VERSION 5.8 ;
BUSBITCHARS "[]" ;
DIVIDERCHAR "/" ;
UNITS
    DATABASE MICRONS 1000 ;
END UNITS

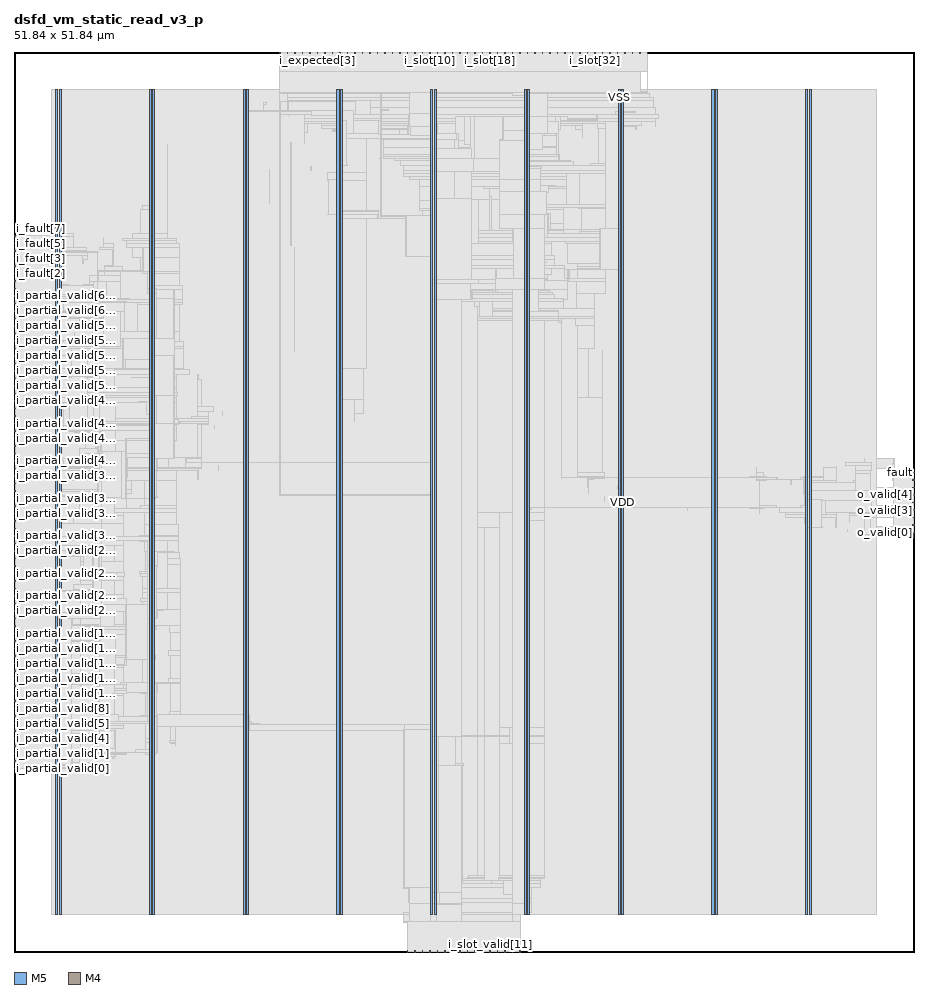
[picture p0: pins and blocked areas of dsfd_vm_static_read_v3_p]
MACRO dsfd_vm_static_read_v3_p
  FOREIGN dsfd_vm_static_read_v3_p 0 0 ;
  CLASS BLOCK ;
  SIZE 51.84 BY 51.84 ;
  PIN ck
    DIRECTION INPUT ;
    USE SIGNAL ;
    PORT
      LAYER M5 ;
        RECT  15.312 51.756 15.336 51.84 ;
    END
  END ck
  PIN fault
    DIRECTION OUTPUT ;
    USE SIGNAL ;
    PORT
      LAYER M4 ;
        RECT  51.756 27.6 51.84 27.624 ;
    END
  END fault
  PIN i_expected[0]
    DIRECTION INPUT ;
    USE SIGNAL ;
    PORT
      LAYER M5 ;
        RECT  16.176 51.756 16.2 51.84 ;
    END
  END i_expected[0]
  PIN i_expected[1]
    DIRECTION INPUT ;
    USE SIGNAL ;
    PORT
      LAYER M5 ;
        RECT  16.608 51.756 16.632 51.84 ;
    END
  END i_expected[1]
  PIN i_expected[2]
    DIRECTION INPUT ;
    USE SIGNAL ;
    PORT
      LAYER M5 ;
        RECT  17.04 51.756 17.064 51.84 ;
    END
  END i_expected[2]
  PIN i_expected[3]
    DIRECTION INPUT ;
    USE SIGNAL ;
    PORT
      LAYER M5 ;
        RECT  17.472 51.756 17.496 51.84 ;
    END
  END i_expected[3]
  PIN i_expected[4]
    DIRECTION INPUT ;
    USE SIGNAL ;
    PORT
      LAYER M5 ;
        RECT  17.904 51.756 17.928 51.84 ;
    END
  END i_expected[4]
  PIN i_expected[5]
    DIRECTION INPUT ;
    USE SIGNAL ;
    PORT
      LAYER M5 ;
        RECT  18.336 51.756 18.36 51.84 ;
    END
  END i_expected[5]
  PIN i_expected[6]
    DIRECTION INPUT ;
    USE SIGNAL ;
    PORT
      LAYER M5 ;
        RECT  18.768 51.756 18.792 51.84 ;
    END
  END i_expected[6]
  PIN i_expected[7]
    DIRECTION INPUT ;
    USE SIGNAL ;
    PORT
      LAYER M5 ;
        RECT  19.2 51.756 19.224 51.84 ;
    END
  END i_expected[7]
  PIN i_fault[0]
    DIRECTION INPUT ;
    USE SIGNAL ;
    PORT
      LAYER M4 ;
        RECT  0 38.208 0.084 38.232 ;
    END
  END i_fault[0]
  PIN i_fault[1]
    DIRECTION INPUT ;
    USE SIGNAL ;
    PORT
      LAYER M4 ;
        RECT  0 38.64 0.084 38.664 ;
    END
  END i_fault[1]
  PIN i_fault[2]
    DIRECTION INPUT ;
    USE SIGNAL ;
    PORT
      LAYER M4 ;
        RECT  0 39.072 0.084 39.096 ;
    END
  END i_fault[2]
  PIN i_fault[3]
    DIRECTION INPUT ;
    USE SIGNAL ;
    PORT
      LAYER M4 ;
        RECT  0 39.504 0.084 39.528 ;
    END
  END i_fault[3]
  PIN i_fault[4]
    DIRECTION INPUT ;
    USE SIGNAL ;
    PORT
      LAYER M4 ;
        RECT  0 39.936 0.084 39.96 ;
    END
  END i_fault[4]
  PIN i_fault[5]
    DIRECTION INPUT ;
    USE SIGNAL ;
    PORT
      LAYER M4 ;
        RECT  0 40.368 0.084 40.392 ;
    END
  END i_fault[5]
  PIN i_fault[6]
    DIRECTION INPUT ;
    USE SIGNAL ;
    PORT
      LAYER M4 ;
        RECT  0 40.8 0.084 40.824 ;
    END
  END i_fault[6]
  PIN i_fault[7]
    DIRECTION INPUT ;
    USE SIGNAL ;
    PORT
      LAYER M4 ;
        RECT  0 41.232 0.084 41.256 ;
    END
  END i_fault[7]
  PIN i_partial_valid[0]
    DIRECTION INPUT ;
    USE SIGNAL ;
    PORT
      LAYER M4 ;
        RECT  0 10.56 0.084 10.584 ;
    END
  END i_partial_valid[0]
  PIN i_partial_valid[10]
    DIRECTION INPUT ;
    USE SIGNAL ;
    PORT
      LAYER M4 ;
        RECT  0 14.88 0.084 14.904 ;
    END
  END i_partial_valid[10]
  PIN i_partial_valid[11]
    DIRECTION INPUT ;
    USE SIGNAL ;
    PORT
      LAYER M4 ;
        RECT  0 15.312 0.084 15.336 ;
    END
  END i_partial_valid[11]
  PIN i_partial_valid[12]
    DIRECTION INPUT ;
    USE SIGNAL ;
    PORT
      LAYER M4 ;
        RECT  0 15.744 0.084 15.768 ;
    END
  END i_partial_valid[12]
  PIN i_partial_valid[13]
    DIRECTION INPUT ;
    USE SIGNAL ;
    PORT
      LAYER M4 ;
        RECT  0 16.176 0.084 16.2 ;
    END
  END i_partial_valid[13]
  PIN i_partial_valid[14]
    DIRECTION INPUT ;
    USE SIGNAL ;
    PORT
      LAYER M4 ;
        RECT  0 16.608 0.084 16.632 ;
    END
  END i_partial_valid[14]
  PIN i_partial_valid[15]
    DIRECTION INPUT ;
    USE SIGNAL ;
    PORT
      LAYER M4 ;
        RECT  0 17.04 0.084 17.064 ;
    END
  END i_partial_valid[15]
  PIN i_partial_valid[16]
    DIRECTION INPUT ;
    USE SIGNAL ;
    PORT
      LAYER M4 ;
        RECT  0 17.472 0.084 17.496 ;
    END
  END i_partial_valid[16]
  PIN i_partial_valid[17]
    DIRECTION INPUT ;
    USE SIGNAL ;
    PORT
      LAYER M4 ;
        RECT  0 17.904 0.084 17.928 ;
    END
  END i_partial_valid[17]
  PIN i_partial_valid[18]
    DIRECTION INPUT ;
    USE SIGNAL ;
    PORT
      LAYER M4 ;
        RECT  0 18.336 0.084 18.36 ;
    END
  END i_partial_valid[18]
  PIN i_partial_valid[19]
    DIRECTION INPUT ;
    USE SIGNAL ;
    PORT
      LAYER M4 ;
        RECT  0 18.768 0.084 18.792 ;
    END
  END i_partial_valid[19]
  PIN i_partial_valid[1]
    DIRECTION INPUT ;
    USE SIGNAL ;
    PORT
      LAYER M4 ;
        RECT  0 10.992 0.084 11.016 ;
    END
  END i_partial_valid[1]
  PIN i_partial_valid[20]
    DIRECTION INPUT ;
    USE SIGNAL ;
    PORT
      LAYER M4 ;
        RECT  0 19.2 0.084 19.224 ;
    END
  END i_partial_valid[20]
  PIN i_partial_valid[21]
    DIRECTION INPUT ;
    USE SIGNAL ;
    PORT
      LAYER M4 ;
        RECT  0 19.632 0.084 19.656 ;
    END
  END i_partial_valid[21]
  PIN i_partial_valid[22]
    DIRECTION INPUT ;
    USE SIGNAL ;
    PORT
      LAYER M4 ;
        RECT  0 20.064 0.084 20.088 ;
    END
  END i_partial_valid[22]
  PIN i_partial_valid[23]
    DIRECTION INPUT ;
    USE SIGNAL ;
    PORT
      LAYER M4 ;
        RECT  0 20.496 0.084 20.52 ;
    END
  END i_partial_valid[23]
  PIN i_partial_valid[24]
    DIRECTION INPUT ;
    USE SIGNAL ;
    PORT
      LAYER M4 ;
        RECT  0 20.928 0.084 20.952 ;
    END
  END i_partial_valid[24]
  PIN i_partial_valid[25]
    DIRECTION INPUT ;
    USE SIGNAL ;
    PORT
      LAYER M4 ;
        RECT  0 21.36 0.084 21.384 ;
    END
  END i_partial_valid[25]
  PIN i_partial_valid[26]
    DIRECTION INPUT ;
    USE SIGNAL ;
    PORT
      LAYER M4 ;
        RECT  0 21.792 0.084 21.816 ;
    END
  END i_partial_valid[26]
  PIN i_partial_valid[27]
    DIRECTION INPUT ;
    USE SIGNAL ;
    PORT
      LAYER M4 ;
        RECT  0 22.224 0.084 22.248 ;
    END
  END i_partial_valid[27]
  PIN i_partial_valid[28]
    DIRECTION INPUT ;
    USE SIGNAL ;
    PORT
      LAYER M4 ;
        RECT  0 22.656 0.084 22.68 ;
    END
  END i_partial_valid[28]
  PIN i_partial_valid[29]
    DIRECTION INPUT ;
    USE SIGNAL ;
    PORT
      LAYER M4 ;
        RECT  0 23.088 0.084 23.112 ;
    END
  END i_partial_valid[29]
  PIN i_partial_valid[2]
    DIRECTION INPUT ;
    USE SIGNAL ;
    PORT
      LAYER M4 ;
        RECT  0 11.424 0.084 11.448 ;
    END
  END i_partial_valid[2]
  PIN i_partial_valid[30]
    DIRECTION INPUT ;
    USE SIGNAL ;
    PORT
      LAYER M4 ;
        RECT  0 23.52 0.084 23.544 ;
    END
  END i_partial_valid[30]
  PIN i_partial_valid[31]
    DIRECTION INPUT ;
    USE SIGNAL ;
    PORT
      LAYER M4 ;
        RECT  0 23.952 0.084 23.976 ;
    END
  END i_partial_valid[31]
  PIN i_partial_valid[32]
    DIRECTION INPUT ;
    USE SIGNAL ;
    PORT
      LAYER M4 ;
        RECT  0 24.384 0.084 24.408 ;
    END
  END i_partial_valid[32]
  PIN i_partial_valid[33]
    DIRECTION INPUT ;
    USE SIGNAL ;
    PORT
      LAYER M4 ;
        RECT  0 24.816 0.084 24.84 ;
    END
  END i_partial_valid[33]
  PIN i_partial_valid[34]
    DIRECTION INPUT ;
    USE SIGNAL ;
    PORT
      LAYER M4 ;
        RECT  0 25.248 0.084 25.272 ;
    END
  END i_partial_valid[34]
  PIN i_partial_valid[35]
    DIRECTION INPUT ;
    USE SIGNAL ;
    PORT
      LAYER M4 ;
        RECT  0 25.68 0.084 25.704 ;
    END
  END i_partial_valid[35]
  PIN i_partial_valid[36]
    DIRECTION INPUT ;
    USE SIGNAL ;
    PORT
      LAYER M4 ;
        RECT  0 26.112 0.084 26.136 ;
    END
  END i_partial_valid[36]
  PIN i_partial_valid[37]
    DIRECTION INPUT ;
    USE SIGNAL ;
    PORT
      LAYER M4 ;
        RECT  0 26.544 0.084 26.568 ;
    END
  END i_partial_valid[37]
  PIN i_partial_valid[38]
    DIRECTION INPUT ;
    USE SIGNAL ;
    PORT
      LAYER M4 ;
        RECT  0 26.976 0.084 27 ;
    END
  END i_partial_valid[38]
  PIN i_partial_valid[39]
    DIRECTION INPUT ;
    USE SIGNAL ;
    PORT
      LAYER M4 ;
        RECT  0 27.408 0.084 27.432 ;
    END
  END i_partial_valid[39]
  PIN i_partial_valid[3]
    DIRECTION INPUT ;
    USE SIGNAL ;
    PORT
      LAYER M4 ;
        RECT  0 11.856 0.084 11.88 ;
    END
  END i_partial_valid[3]
  PIN i_partial_valid[40]
    DIRECTION INPUT ;
    USE SIGNAL ;
    PORT
      LAYER M4 ;
        RECT  0 27.84 0.084 27.864 ;
    END
  END i_partial_valid[40]
  PIN i_partial_valid[41]
    DIRECTION INPUT ;
    USE SIGNAL ;
    PORT
      LAYER M4 ;
        RECT  0 28.272 0.084 28.296 ;
    END
  END i_partial_valid[41]
  PIN i_partial_valid[42]
    DIRECTION INPUT ;
    USE SIGNAL ;
    PORT
      LAYER M4 ;
        RECT  0 28.704 0.084 28.728 ;
    END
  END i_partial_valid[42]
  PIN i_partial_valid[43]
    DIRECTION INPUT ;
    USE SIGNAL ;
    PORT
      LAYER M4 ;
        RECT  0 29.136 0.084 29.16 ;
    END
  END i_partial_valid[43]
  PIN i_partial_valid[44]
    DIRECTION INPUT ;
    USE SIGNAL ;
    PORT
      LAYER M4 ;
        RECT  0 29.568 0.084 29.592 ;
    END
  END i_partial_valid[44]
  PIN i_partial_valid[45]
    DIRECTION INPUT ;
    USE SIGNAL ;
    PORT
      LAYER M4 ;
        RECT  0 30 0.084 30.024 ;
    END
  END i_partial_valid[45]
  PIN i_partial_valid[46]
    DIRECTION INPUT ;
    USE SIGNAL ;
    PORT
      LAYER M4 ;
        RECT  0 30.432 0.084 30.456 ;
    END
  END i_partial_valid[46]
  PIN i_partial_valid[47]
    DIRECTION INPUT ;
    USE SIGNAL ;
    PORT
      LAYER M4 ;
        RECT  0 30.864 0.084 30.888 ;
    END
  END i_partial_valid[47]
  PIN i_partial_valid[48]
    DIRECTION INPUT ;
    USE SIGNAL ;
    PORT
      LAYER M4 ;
        RECT  0 31.296 0.084 31.32 ;
    END
  END i_partial_valid[48]
  PIN i_partial_valid[49]
    DIRECTION INPUT ;
    USE SIGNAL ;
    PORT
      LAYER M4 ;
        RECT  0 31.728 0.084 31.752 ;
    END
  END i_partial_valid[49]
  PIN i_partial_valid[4]
    DIRECTION INPUT ;
    USE SIGNAL ;
    PORT
      LAYER M4 ;
        RECT  0 12.288 0.084 12.312 ;
    END
  END i_partial_valid[4]
  PIN i_partial_valid[50]
    DIRECTION INPUT ;
    USE SIGNAL ;
    PORT
      LAYER M4 ;
        RECT  0 32.16 0.084 32.184 ;
    END
  END i_partial_valid[50]
  PIN i_partial_valid[51]
    DIRECTION INPUT ;
    USE SIGNAL ;
    PORT
      LAYER M4 ;
        RECT  0 32.592 0.084 32.616 ;
    END
  END i_partial_valid[51]
  PIN i_partial_valid[52]
    DIRECTION INPUT ;
    USE SIGNAL ;
    PORT
      LAYER M4 ;
        RECT  0 33.024 0.084 33.048 ;
    END
  END i_partial_valid[52]
  PIN i_partial_valid[53]
    DIRECTION INPUT ;
    USE SIGNAL ;
    PORT
      LAYER M4 ;
        RECT  0 33.456 0.084 33.48 ;
    END
  END i_partial_valid[53]
  PIN i_partial_valid[54]
    DIRECTION INPUT ;
    USE SIGNAL ;
    PORT
      LAYER M4 ;
        RECT  0 33.888 0.084 33.912 ;
    END
  END i_partial_valid[54]
  PIN i_partial_valid[55]
    DIRECTION INPUT ;
    USE SIGNAL ;
    PORT
      LAYER M4 ;
        RECT  0 34.32 0.084 34.344 ;
    END
  END i_partial_valid[55]
  PIN i_partial_valid[56]
    DIRECTION INPUT ;
    USE SIGNAL ;
    PORT
      LAYER M4 ;
        RECT  0 34.752 0.084 34.776 ;
    END
  END i_partial_valid[56]
  PIN i_partial_valid[57]
    DIRECTION INPUT ;
    USE SIGNAL ;
    PORT
      LAYER M4 ;
        RECT  0 35.184 0.084 35.208 ;
    END
  END i_partial_valid[57]
  PIN i_partial_valid[58]
    DIRECTION INPUT ;
    USE SIGNAL ;
    PORT
      LAYER M4 ;
        RECT  0 35.616 0.084 35.64 ;
    END
  END i_partial_valid[58]
  PIN i_partial_valid[59]
    DIRECTION INPUT ;
    USE SIGNAL ;
    PORT
      LAYER M4 ;
        RECT  0 36.048 0.084 36.072 ;
    END
  END i_partial_valid[59]
  PIN i_partial_valid[5]
    DIRECTION INPUT ;
    USE SIGNAL ;
    PORT
      LAYER M4 ;
        RECT  0 12.72 0.084 12.744 ;
    END
  END i_partial_valid[5]
  PIN i_partial_valid[60]
    DIRECTION INPUT ;
    USE SIGNAL ;
    PORT
      LAYER M4 ;
        RECT  0 36.48 0.084 36.504 ;
    END
  END i_partial_valid[60]
  PIN i_partial_valid[61]
    DIRECTION INPUT ;
    USE SIGNAL ;
    PORT
      LAYER M4 ;
        RECT  0 36.912 0.084 36.936 ;
    END
  END i_partial_valid[61]
  PIN i_partial_valid[62]
    DIRECTION INPUT ;
    USE SIGNAL ;
    PORT
      LAYER M4 ;
        RECT  0 37.344 0.084 37.368 ;
    END
  END i_partial_valid[62]
  PIN i_partial_valid[63]
    DIRECTION INPUT ;
    USE SIGNAL ;
    PORT
      LAYER M4 ;
        RECT  0 37.776 0.084 37.8 ;
    END
  END i_partial_valid[63]
  PIN i_partial_valid[6]
    DIRECTION INPUT ;
    USE SIGNAL ;
    PORT
      LAYER M4 ;
        RECT  0 13.152 0.084 13.176 ;
    END
  END i_partial_valid[6]
  PIN i_partial_valid[7]
    DIRECTION INPUT ;
    USE SIGNAL ;
    PORT
      LAYER M4 ;
        RECT  0 13.584 0.084 13.608 ;
    END
  END i_partial_valid[7]
  PIN i_partial_valid[8]
    DIRECTION INPUT ;
    USE SIGNAL ;
    PORT
      LAYER M4 ;
        RECT  0 14.016 0.084 14.04 ;
    END
  END i_partial_valid[8]
  PIN i_partial_valid[9]
    DIRECTION INPUT ;
    USE SIGNAL ;
    PORT
      LAYER M4 ;
        RECT  0 14.448 0.084 14.472 ;
    END
  END i_partial_valid[9]
  PIN i_slot[0]
    DIRECTION INPUT ;
    USE SIGNAL ;
    PORT
      LAYER M5 ;
        RECT  19.632 51.756 19.656 51.84 ;
    END
  END i_slot[0]
  PIN i_slot[10]
    DIRECTION INPUT ;
    USE SIGNAL ;
    PORT
      LAYER M5 ;
        RECT  23.952 51.756 23.976 51.84 ;
    END
  END i_slot[10]
  PIN i_slot[11]
    DIRECTION INPUT ;
    USE SIGNAL ;
    PORT
      LAYER M5 ;
        RECT  24.384 51.756 24.408 51.84 ;
    END
  END i_slot[11]
  PIN i_slot[12]
    DIRECTION INPUT ;
    USE SIGNAL ;
    PORT
      LAYER M5 ;
        RECT  24.816 51.756 24.84 51.84 ;
    END
  END i_slot[12]
  PIN i_slot[13]
    DIRECTION INPUT ;
    USE SIGNAL ;
    PORT
      LAYER M5 ;
        RECT  25.248 51.756 25.272 51.84 ;
    END
  END i_slot[13]
  PIN i_slot[14]
    DIRECTION INPUT ;
    USE SIGNAL ;
    PORT
      LAYER M5 ;
        RECT  25.68 51.756 25.704 51.84 ;
    END
  END i_slot[14]
  PIN i_slot[15]
    DIRECTION INPUT ;
    USE SIGNAL ;
    PORT
      LAYER M5 ;
        RECT  26.112 51.756 26.136 51.84 ;
    END
  END i_slot[15]
  PIN i_slot[16]
    DIRECTION INPUT ;
    USE SIGNAL ;
    PORT
      LAYER M5 ;
        RECT  26.544 51.756 26.568 51.84 ;
    END
  END i_slot[16]
  PIN i_slot[17]
    DIRECTION INPUT ;
    USE SIGNAL ;
    PORT
      LAYER M5 ;
        RECT  26.976 51.756 27 51.84 ;
    END
  END i_slot[17]
  PIN i_slot[18]
    DIRECTION INPUT ;
    USE SIGNAL ;
    PORT
      LAYER M5 ;
        RECT  27.408 51.756 27.432 51.84 ;
    END
  END i_slot[18]
  PIN i_slot[19]
    DIRECTION INPUT ;
    USE SIGNAL ;
    PORT
      LAYER M5 ;
        RECT  27.84 51.756 27.864 51.84 ;
    END
  END i_slot[19]
  PIN i_slot[1]
    DIRECTION INPUT ;
    USE SIGNAL ;
    PORT
      LAYER M5 ;
        RECT  20.064 51.756 20.088 51.84 ;
    END
  END i_slot[1]
  PIN i_slot[20]
    DIRECTION INPUT ;
    USE SIGNAL ;
    PORT
      LAYER M5 ;
        RECT  28.272 51.756 28.296 51.84 ;
    END
  END i_slot[20]
  PIN i_slot[21]
    DIRECTION INPUT ;
    USE SIGNAL ;
    PORT
      LAYER M5 ;
        RECT  28.704 51.756 28.728 51.84 ;
    END
  END i_slot[21]
  PIN i_slot[22]
    DIRECTION INPUT ;
    USE SIGNAL ;
    PORT
      LAYER M5 ;
        RECT  29.136 51.756 29.16 51.84 ;
    END
  END i_slot[22]
  PIN i_slot[23]
    DIRECTION INPUT ;
    USE SIGNAL ;
    PORT
      LAYER M5 ;
        RECT  29.568 51.756 29.592 51.84 ;
    END
  END i_slot[23]
  PIN i_slot[24]
    DIRECTION INPUT ;
    USE SIGNAL ;
    PORT
      LAYER M5 ;
        RECT  30 51.756 30.024 51.84 ;
    END
  END i_slot[24]
  PIN i_slot[25]
    DIRECTION INPUT ;
    USE SIGNAL ;
    PORT
      LAYER M5 ;
        RECT  30.432 51.756 30.456 51.84 ;
    END
  END i_slot[25]
  PIN i_slot[26]
    DIRECTION INPUT ;
    USE SIGNAL ;
    PORT
      LAYER M5 ;
        RECT  30.864 51.756 30.888 51.84 ;
    END
  END i_slot[26]
  PIN i_slot[27]
    DIRECTION INPUT ;
    USE SIGNAL ;
    PORT
      LAYER M5 ;
        RECT  31.296 51.756 31.32 51.84 ;
    END
  END i_slot[27]
  PIN i_slot[28]
    DIRECTION INPUT ;
    USE SIGNAL ;
    PORT
      LAYER M5 ;
        RECT  31.728 51.756 31.752 51.84 ;
    END
  END i_slot[28]
  PIN i_slot[29]
    DIRECTION INPUT ;
    USE SIGNAL ;
    PORT
      LAYER M5 ;
        RECT  32.16 51.756 32.184 51.84 ;
    END
  END i_slot[29]
  PIN i_slot[2]
    DIRECTION INPUT ;
    USE SIGNAL ;
    PORT
      LAYER M5 ;
        RECT  20.496 51.756 20.52 51.84 ;
    END
  END i_slot[2]
  PIN i_slot[30]
    DIRECTION INPUT ;
    USE SIGNAL ;
    PORT
      LAYER M5 ;
        RECT  32.592 51.756 32.616 51.84 ;
    END
  END i_slot[30]
  PIN i_slot[31]
    DIRECTION INPUT ;
    USE SIGNAL ;
    PORT
      LAYER M5 ;
        RECT  33.024 51.756 33.048 51.84 ;
    END
  END i_slot[31]
  PIN i_slot[32]
    DIRECTION INPUT ;
    USE SIGNAL ;
    PORT
      LAYER M5 ;
        RECT  33.456 51.756 33.48 51.84 ;
    END
  END i_slot[32]
  PIN i_slot[33]
    DIRECTION INPUT ;
    USE SIGNAL ;
    PORT
      LAYER M5 ;
        RECT  33.888 51.756 33.912 51.84 ;
    END
  END i_slot[33]
  PIN i_slot[34]
    DIRECTION INPUT ;
    USE SIGNAL ;
    PORT
      LAYER M5 ;
        RECT  34.32 51.756 34.344 51.84 ;
    END
  END i_slot[34]
  PIN i_slot[35]
    DIRECTION INPUT ;
    USE SIGNAL ;
    PORT
      LAYER M5 ;
        RECT  34.752 51.756 34.776 51.84 ;
    END
  END i_slot[35]
  PIN i_slot[36]
    DIRECTION INPUT ;
    USE SIGNAL ;
    PORT
      LAYER M5 ;
        RECT  35.184 51.756 35.208 51.84 ;
    END
  END i_slot[36]
  PIN i_slot[37]
    DIRECTION INPUT ;
    USE SIGNAL ;
    PORT
      LAYER M5 ;
        RECT  35.616 51.756 35.64 51.84 ;
    END
  END i_slot[37]
  PIN i_slot[38]
    DIRECTION INPUT ;
    USE SIGNAL ;
    PORT
      LAYER M5 ;
        RECT  36.048 51.756 36.072 51.84 ;
    END
  END i_slot[38]
  PIN i_slot[39]
    DIRECTION INPUT ;
    USE SIGNAL ;
    PORT
      LAYER M5 ;
        RECT  36.48 51.756 36.504 51.84 ;
    END
  END i_slot[39]
  PIN i_slot[3]
    DIRECTION INPUT ;
    USE SIGNAL ;
    PORT
      LAYER M5 ;
        RECT  20.928 51.756 20.952 51.84 ;
    END
  END i_slot[3]
  PIN i_slot[4]
    DIRECTION INPUT ;
    USE SIGNAL ;
    PORT
      LAYER M5 ;
        RECT  21.36 51.756 21.384 51.84 ;
    END
  END i_slot[4]
  PIN i_slot[5]
    DIRECTION INPUT ;
    USE SIGNAL ;
    PORT
      LAYER M5 ;
        RECT  21.792 51.756 21.816 51.84 ;
    END
  END i_slot[5]
  PIN i_slot[6]
    DIRECTION INPUT ;
    USE SIGNAL ;
    PORT
      LAYER M5 ;
        RECT  22.224 51.756 22.248 51.84 ;
    END
  END i_slot[6]
  PIN i_slot[7]
    DIRECTION INPUT ;
    USE SIGNAL ;
    PORT
      LAYER M5 ;
        RECT  22.656 51.756 22.68 51.84 ;
    END
  END i_slot[7]
  PIN i_slot[8]
    DIRECTION INPUT ;
    USE SIGNAL ;
    PORT
      LAYER M5 ;
        RECT  23.088 51.756 23.112 51.84 ;
    END
  END i_slot[8]
  PIN i_slot[9]
    DIRECTION INPUT ;
    USE SIGNAL ;
    PORT
      LAYER M5 ;
        RECT  23.52 51.756 23.544 51.84 ;
    END
  END i_slot[9]
  PIN i_slot_valid[0]
    DIRECTION INPUT ;
    USE SIGNAL ;
    PORT
      LAYER M5 ;
        RECT  22.656 0 22.68 0.084 ;
    END
  END i_slot_valid[0]
  PIN i_slot_valid[10]
    DIRECTION INPUT ;
    USE SIGNAL ;
    PORT
      LAYER M5 ;
        RECT  26.976 0 27 0.084 ;
    END
  END i_slot_valid[10]
  PIN i_slot_valid[11]
    DIRECTION INPUT ;
    USE SIGNAL ;
    PORT
      LAYER M5 ;
        RECT  27.408 0 27.432 0.084 ;
    END
  END i_slot_valid[11]
  PIN i_slot_valid[12]
    DIRECTION INPUT ;
    USE SIGNAL ;
    PORT
      LAYER M5 ;
        RECT  27.84 0 27.864 0.084 ;
    END
  END i_slot_valid[12]
  PIN i_slot_valid[13]
    DIRECTION INPUT ;
    USE SIGNAL ;
    PORT
      LAYER M5 ;
        RECT  28.272 0 28.296 0.084 ;
    END
  END i_slot_valid[13]
  PIN i_slot_valid[14]
    DIRECTION INPUT ;
    USE SIGNAL ;
    PORT
      LAYER M5 ;
        RECT  28.704 0 28.728 0.084 ;
    END
  END i_slot_valid[14]
  PIN i_slot_valid[15]
    DIRECTION INPUT ;
    USE SIGNAL ;
    PORT
      LAYER M5 ;
        RECT  29.136 0 29.16 0.084 ;
    END
  END i_slot_valid[15]
  PIN i_slot_valid[1]
    DIRECTION INPUT ;
    USE SIGNAL ;
    PORT
      LAYER M5 ;
        RECT  23.088 0 23.112 0.084 ;
    END
  END i_slot_valid[1]
  PIN i_slot_valid[2]
    DIRECTION INPUT ;
    USE SIGNAL ;
    PORT
      LAYER M5 ;
        RECT  23.52 0 23.544 0.084 ;
    END
  END i_slot_valid[2]
  PIN i_slot_valid[3]
    DIRECTION INPUT ;
    USE SIGNAL ;
    PORT
      LAYER M5 ;
        RECT  23.952 0 23.976 0.084 ;
    END
  END i_slot_valid[3]
  PIN i_slot_valid[4]
    DIRECTION INPUT ;
    USE SIGNAL ;
    PORT
      LAYER M5 ;
        RECT  24.384 0 24.408 0.084 ;
    END
  END i_slot_valid[4]
  PIN i_slot_valid[5]
    DIRECTION INPUT ;
    USE SIGNAL ;
    PORT
      LAYER M5 ;
        RECT  24.816 0 24.84 0.084 ;
    END
  END i_slot_valid[5]
  PIN i_slot_valid[6]
    DIRECTION INPUT ;
    USE SIGNAL ;
    PORT
      LAYER M5 ;
        RECT  25.248 0 25.272 0.084 ;
    END
  END i_slot_valid[6]
  PIN i_slot_valid[7]
    DIRECTION INPUT ;
    USE SIGNAL ;
    PORT
      LAYER M5 ;
        RECT  25.68 0 25.704 0.084 ;
    END
  END i_slot_valid[7]
  PIN i_slot_valid[8]
    DIRECTION INPUT ;
    USE SIGNAL ;
    PORT
      LAYER M5 ;
        RECT  26.112 0 26.136 0.084 ;
    END
  END i_slot_valid[8]
  PIN i_slot_valid[9]
    DIRECTION INPUT ;
    USE SIGNAL ;
    PORT
      LAYER M5 ;
        RECT  26.544 0 26.568 0.084 ;
    END
  END i_slot_valid[9]
  PIN o_valid[0]
    DIRECTION OUTPUT ;
    USE SIGNAL ;
    PORT
      LAYER M4 ;
        RECT  51.756 24.144 51.84 24.168 ;
    END
  END o_valid[0]
  PIN o_valid[1]
    DIRECTION OUTPUT ;
    USE SIGNAL ;
    PORT
      LAYER M4 ;
        RECT  51.756 24.576 51.84 24.6 ;
    END
  END o_valid[1]
  PIN o_valid[2]
    DIRECTION OUTPUT ;
    USE SIGNAL ;
    PORT
      LAYER M4 ;
        RECT  51.756 25.008 51.84 25.032 ;
    END
  END o_valid[2]
  PIN o_valid[3]
    DIRECTION OUTPUT ;
    USE SIGNAL ;
    PORT
      LAYER M4 ;
        RECT  51.756 25.44 51.84 25.464 ;
    END
  END o_valid[3]
  PIN o_valid[4]
    DIRECTION OUTPUT ;
    USE SIGNAL ;
    PORT
      LAYER M4 ;
        RECT  51.756 25.872 51.84 25.896 ;
    END
  END o_valid[4]
  PIN o_valid[5]
    DIRECTION OUTPUT ;
    USE SIGNAL ;
    PORT
      LAYER M4 ;
        RECT  51.756 26.304 51.84 26.328 ;
    END
  END o_valid[5]
  PIN o_valid[6]
    DIRECTION OUTPUT ;
    USE SIGNAL ;
    PORT
      LAYER M4 ;
        RECT  51.756 26.736 51.84 26.76 ;
    END
  END o_valid[6]
  PIN o_valid[7]
    DIRECTION OUTPUT ;
    USE SIGNAL ;
    PORT
      LAYER M4 ;
        RECT  51.756 27.168 51.84 27.192 ;
    END
  END o_valid[7]
  PIN rst_n
    DIRECTION INPUT ;
    USE SIGNAL ;
    PORT
      LAYER M5 ;
        RECT  15.744 51.756 15.768 51.84 ;
    END
  END rst_n
  PIN VDD
    DIRECTION INOUT ;
    USE POWER ;
    PORT
      LAYER M5 ;
        RECT  45.792 2.151 45.912 49.689 ;
        RECT  40.392 2.151 40.512 49.689 ;
        RECT  34.992 2.151 35.112 49.689 ;
        RECT  29.592 2.151 29.712 49.689 ;
        RECT  24.192 2.151 24.312 49.689 ;
        RECT  18.792 2.151 18.912 49.689 ;
        RECT  13.392 2.151 13.512 49.689 ;
        RECT  7.992 2.151 8.112 49.689 ;
        RECT  2.592 2.151 2.712 49.689 ;
    END
  END VDD
  PIN VSS
    DIRECTION INOUT ;
    USE GROUND ;
    PORT
      LAYER M5 ;
        RECT  45.6 2.137 45.72 49.703 ;
        RECT  40.2 2.137 40.32 49.703 ;
        RECT  34.8 2.137 34.92 49.703 ;
        RECT  29.4 2.137 29.52 49.703 ;
        RECT  24 2.137 24.12 49.703 ;
        RECT  18.6 2.137 18.72 49.703 ;
        RECT  13.2 2.137 13.32 49.703 ;
        RECT  7.8 2.137 7.92 49.703 ;
        RECT  2.4 2.137 2.52 49.703 ;
    END
  END VSS
  # OT_OBS_CLOSED layer=M5 d_um=1.536 added=42
  OBS
    LAYER RVTN ;
     RECT  2.16 2.16 49.68 2.295 ;
     RECT  2.16 2.565 49.68 2.835 ;
     RECT  2.16 3.105 49.68 3.375 ;
     RECT  2.16 3.645 49.68 3.915 ;
     RECT  2.16 4.185 49.68 4.455 ;
     RECT  2.16 4.725 49.68 4.995 ;
     RECT  2.16 5.265 49.68 5.535 ;
     RECT  2.16 5.805 49.68 6.075 ;
     RECT  2.16 6.345 49.68 6.615 ;
     RECT  2.16 6.885 49.68 7.155 ;
     RECT  2.16 7.425 49.68 7.695 ;
     RECT  2.16 7.965 49.68 8.235 ;
     RECT  2.16 8.505 49.68 8.775 ;
     RECT  2.16 9.045 49.68 9.315 ;
     RECT  2.16 9.585 49.68 9.855 ;
     RECT  2.16 10.125 49.68 10.395 ;
     RECT  2.16 10.665 49.68 10.935 ;
     RECT  2.16 11.205 49.68 11.475 ;
     RECT  2.16 11.745 49.68 12.015 ;
     RECT  2.16 12.285 49.68 12.555 ;
     RECT  2.16 12.825 49.68 13.095 ;
     RECT  2.16 13.365 49.68 13.635 ;
     RECT  2.16 13.905 49.68 14.175 ;
     RECT  2.16 14.445 49.68 14.715 ;
     RECT  2.16 14.985 49.68 15.255 ;
     RECT  2.16 15.525 49.68 15.795 ;
     RECT  2.16 16.065 49.68 16.335 ;
     RECT  2.16 16.605 49.68 16.875 ;
     RECT  2.16 17.145 49.68 17.415 ;
     RECT  2.16 17.685 49.68 17.955 ;
     RECT  2.16 18.225 49.68 18.495 ;
     RECT  2.16 18.765 49.68 19.035 ;
     RECT  2.16 19.305 49.68 19.575 ;
     RECT  2.16 19.845 49.68 20.115 ;
     RECT  2.16 20.385 49.68 20.655 ;
     RECT  2.16 20.925 49.68 21.195 ;
     RECT  2.16 21.465 49.68 21.735 ;
     RECT  2.16 22.005 49.68 22.275 ;
     RECT  2.16 22.545 49.68 22.815 ;
     RECT  2.16 23.085 49.68 23.355 ;
     RECT  2.16 23.625 49.68 23.895 ;
     RECT  2.16 24.165 49.68 24.435 ;
     RECT  2.16 24.705 49.68 24.975 ;
     RECT  2.16 25.245 49.68 25.515 ;
     RECT  2.16 25.785 49.68 26.055 ;
     RECT  2.16 26.325 49.68 26.595 ;
     RECT  2.16 26.865 49.68 27.135 ;
     RECT  2.16 27.405 49.68 27.675 ;
     RECT  2.16 27.945 49.68 28.215 ;
     RECT  2.16 28.485 49.68 28.755 ;
     RECT  2.16 29.025 49.68 29.295 ;
     RECT  2.16 29.565 49.68 29.835 ;
     RECT  2.16 30.105 49.68 30.375 ;
     RECT  2.16 30.645 49.68 30.915 ;
     RECT  2.16 31.185 49.68 31.455 ;
     RECT  2.16 31.725 49.68 31.995 ;
     RECT  2.16 32.265 49.68 32.535 ;
     RECT  2.16 32.805 49.68 33.075 ;
     RECT  2.16 33.345 49.68 33.615 ;
     RECT  2.16 33.885 49.68 34.155 ;
     RECT  2.16 34.425 49.68 34.695 ;
     RECT  2.16 34.965 49.68 35.235 ;
     RECT  2.16 35.505 49.68 35.775 ;
     RECT  2.16 36.045 49.68 36.315 ;
     RECT  2.16 36.585 49.68 36.855 ;
     RECT  2.16 37.125 49.68 37.395 ;
     RECT  2.16 37.665 49.68 37.935 ;
     RECT  2.16 38.205 49.68 38.475 ;
     RECT  2.16 38.745 49.68 39.015 ;
     RECT  2.16 39.285 49.68 39.555 ;
     RECT  2.16 39.825 49.68 40.095 ;
     RECT  2.16 40.365 49.68 40.635 ;
     RECT  2.16 40.905 49.68 41.175 ;
     RECT  2.16 41.445 49.68 41.715 ;
     RECT  2.16 41.985 49.68 42.255 ;
     RECT  2.16 42.525 49.68 42.795 ;
     RECT  2.16 43.065 49.68 43.335 ;
     RECT  2.16 43.605 49.68 43.875 ;
     RECT  2.16 44.145 49.68 44.415 ;
     RECT  2.16 44.685 49.68 44.955 ;
     RECT  2.16 45.225 49.68 45.495 ;
     RECT  2.16 45.765 49.68 46.035 ;
     RECT  2.16 46.305 49.68 46.575 ;
     RECT  2.16 46.845 49.68 47.115 ;
     RECT  2.16 47.385 49.68 47.655 ;
     RECT  2.16 47.925 49.68 48.195 ;
     RECT  2.16 48.465 49.68 48.735 ;
     RECT  2.16 49.005 49.68 49.275 ;
     RECT  2.16 49.545 49.68 49.68 ;
    LAYER RVTP ;
     RECT  2.16 2.295 49.68 2.565 ;
     RECT  2.16 2.835 49.68 3.105 ;
     RECT  2.16 3.375 49.68 3.645 ;
     RECT  2.16 3.915 49.68 4.185 ;
     RECT  2.16 4.455 49.68 4.725 ;
     RECT  2.16 4.995 49.68 5.265 ;
     RECT  2.16 5.535 49.68 5.805 ;
     RECT  2.16 6.075 49.68 6.345 ;
     RECT  2.16 6.615 49.68 6.885 ;
     RECT  2.16 7.155 49.68 7.425 ;
     RECT  2.16 7.695 49.68 7.965 ;
     RECT  2.16 8.235 49.68 8.505 ;
     RECT  2.16 8.775 49.68 9.045 ;
     RECT  2.16 9.315 49.68 9.585 ;
     RECT  2.16 9.855 49.68 10.125 ;
     RECT  2.16 10.395 49.68 10.665 ;
     RECT  2.16 10.935 49.68 11.205 ;
     RECT  2.16 11.475 49.68 11.745 ;
     RECT  2.16 12.015 49.68 12.285 ;
     RECT  2.16 12.555 49.68 12.825 ;
     RECT  2.16 13.095 49.68 13.365 ;
     RECT  2.16 13.635 49.68 13.905 ;
     RECT  2.16 14.175 49.68 14.445 ;
     RECT  2.16 14.715 49.68 14.985 ;
     RECT  2.16 15.255 49.68 15.525 ;
     RECT  2.16 15.795 49.68 16.065 ;
     RECT  2.16 16.335 49.68 16.605 ;
     RECT  2.16 16.875 49.68 17.145 ;
     RECT  2.16 17.415 49.68 17.685 ;
     RECT  2.16 17.955 49.68 18.225 ;
     RECT  2.16 18.495 49.68 18.765 ;
     RECT  2.16 19.035 49.68 19.305 ;
     RECT  2.16 19.575 49.68 19.845 ;
     RECT  2.16 20.115 49.68 20.385 ;
     RECT  2.16 20.655 49.68 20.925 ;
     RECT  2.16 21.195 49.68 21.465 ;
     RECT  2.16 21.735 49.68 22.005 ;
     RECT  2.16 22.275 49.68 22.545 ;
     RECT  2.16 22.815 49.68 23.085 ;
     RECT  2.16 23.355 49.68 23.625 ;
     RECT  2.16 23.895 49.68 24.165 ;
     RECT  2.16 24.435 49.68 24.705 ;
     RECT  2.16 24.975 49.68 25.245 ;
     RECT  2.16 25.515 49.68 25.785 ;
     RECT  2.16 26.055 49.68 26.325 ;
     RECT  2.16 26.595 49.68 26.865 ;
     RECT  2.16 27.135 49.68 27.405 ;
     RECT  2.16 27.675 49.68 27.945 ;
     RECT  2.16 28.215 49.68 28.485 ;
     RECT  2.16 28.755 49.68 29.025 ;
     RECT  2.16 29.295 49.68 29.565 ;
     RECT  2.16 29.835 49.68 30.105 ;
     RECT  2.16 30.375 49.68 30.645 ;
     RECT  2.16 30.915 49.68 31.185 ;
     RECT  2.16 31.455 49.68 31.725 ;
     RECT  2.16 31.995 49.68 32.265 ;
     RECT  2.16 32.535 49.68 32.805 ;
     RECT  2.16 33.075 49.68 33.345 ;
     RECT  2.16 33.615 49.68 33.885 ;
     RECT  2.16 34.155 49.68 34.425 ;
     RECT  2.16 34.695 49.68 34.965 ;
     RECT  2.16 35.235 49.68 35.505 ;
     RECT  2.16 35.775 49.68 36.045 ;
     RECT  2.16 36.315 49.68 36.585 ;
     RECT  2.16 36.855 49.68 37.125 ;
     RECT  2.16 37.395 49.68 37.665 ;
     RECT  2.16 37.935 49.68 38.205 ;
     RECT  2.16 38.475 49.68 38.745 ;
     RECT  2.16 39.015 49.68 39.285 ;
     RECT  2.16 39.555 49.68 39.825 ;
     RECT  2.16 40.095 49.68 40.365 ;
     RECT  2.16 40.635 49.68 40.905 ;
     RECT  2.16 41.175 49.68 41.445 ;
     RECT  2.16 41.715 49.68 41.985 ;
     RECT  2.16 42.255 49.68 42.525 ;
     RECT  2.16 42.795 49.68 43.065 ;
     RECT  2.16 43.335 49.68 43.605 ;
     RECT  2.16 43.875 49.68 44.145 ;
     RECT  2.16 44.415 49.68 44.685 ;
     RECT  2.16 44.955 49.68 45.225 ;
     RECT  2.16 45.495 49.68 45.765 ;
     RECT  2.16 46.035 49.68 46.305 ;
     RECT  2.16 46.575 49.68 46.845 ;
     RECT  2.16 47.115 49.68 47.385 ;
     RECT  2.16 47.655 49.68 47.925 ;
     RECT  2.16 48.195 49.68 48.465 ;
     RECT  2.16 48.735 49.68 49.005 ;
     RECT  2.16 49.275 49.68 49.545 ;
    LAYER M1 ;
     RECT  2.16 2.151 49.68 49.689 ;
    LAYER M2 ;
     RECT  0.103 13.032 2.16 13.05 ;
     RECT  0.535 22.212 2.16 22.23 ;
     RECT  0.103 38.142 2.16 38.16 ;
     RECT  2.16 2.151 49.68 49.689 ;
     RECT  49.68 27.846 50.675 28.404 ;
     RECT  49.68 24.138 50.711 24.498 ;
     RECT  49.68 25.326 50.711 25.704 ;
     RECT  49.68 26.766 50.711 26.784 ;
     RECT  50.675 28.386 50.711 28.404 ;
     RECT  50.711 24.48 50.747 24.498 ;
     RECT  50.711 25.326 50.747 25.344 ;
    LAYER M3 ;
     RECT  25.668 0.571 25.686 1.723 ;
     RECT  22.428 1.723 29.142 2.143 ;
     RECT  22.428 2.143 29.505 2.255 ;
     RECT  22.752 2.255 29.505 2.263 ;
     RECT  2.415 2.143 2.505 2.413 ;
     RECT  7.815 2.143 7.905 2.413 ;
     RECT  13.215 2.143 13.305 2.413 ;
     RECT  18.615 2.143 18.705 2.413 ;
     RECT  34.815 2.143 34.905 2.413 ;
     RECT  40.215 2.143 40.305 2.413 ;
     RECT  45.615 2.143 45.705 2.413 ;
     RECT  22.752 2.263 29.79 2.861 ;
     RECT  22.968 2.861 29.79 3.065 ;
     RECT  23.184 3.065 29.79 3.721 ;
     RECT  23.184 3.721 30.33 3.725 ;
     RECT  23.616 3.725 30.33 3.965 ;
     RECT  24.015 3.965 30.33 4.115 ;
     RECT  24.015 4.115 27.09 4.253 ;
     RECT  27.9 4.115 30.33 4.261 ;
     RECT  26.1 4.253 27.09 4.289 ;
     RECT  27.9 4.261 30.546 4.289 ;
     RECT  26.172 4.289 27.09 4.415 ;
     RECT  27.936 4.289 30.546 4.415 ;
     RECT  2.415 2.413 2.697 10.555 ;
     RECT  2.304 10.555 2.697 10.597 ;
     RECT  2.304 10.597 3.294 10.625 ;
     RECT  2.415 10.625 3.294 10.633 ;
     RECT  4.068 10.597 4.086 10.633 ;
     RECT  2.415 10.633 4.086 10.741 ;
     RECT  24.015 4.253 25.362 10.741 ;
     RECT  24.015 10.741 25.902 10.882 ;
     RECT  2.415 10.741 4.806 10.895 ;
     RECT  5.652 11.137 5.67 11.173 ;
     RECT  3.744 10.895 4.806 11.209 ;
     RECT  3.744 11.209 4.842 11.281 ;
     RECT  5.652 11.173 5.814 11.281 ;
     RECT  3.744 11.281 5.85 11.371 ;
     RECT  7.815 2.413 8.097 11.371 ;
     RECT  3.744 11.371 6.462 11.435 ;
     RECT  2.415 10.895 2.826 11.453 ;
     RECT  3.744 11.435 3.834 11.453 ;
     RECT  4.788 11.435 6.462 11.479 ;
     RECT  7.56 11.371 8.097 11.479 ;
     RECT  4.788 11.479 8.097 11.501 ;
     RECT  7.02 11.501 8.097 11.669 ;
     RECT  4.788 11.501 5.85 11.705 ;
     RECT  2.415 11.453 2.697 11.851 ;
     RECT  27.936 4.415 27.954 11.995 ;
     RECT  28.764 4.415 30.546 11.995 ;
     RECT  9.288 11.911 9.306 12.019 ;
     RECT  9.036 12.019 9.306 12.055 ;
     RECT  7.56 11.669 8.097 12.091 ;
     RECT  8.928 12.055 9.306 12.209 ;
     RECT  7.56 12.091 8.154 12.269 ;
     RECT  3.816 11.453 3.834 12.361 ;
     RECT  26.676 4.415 27.09 12.427 ;
     RECT  27.936 11.995 30.546 12.427 ;
     RECT  4.788 11.705 4.806 12.451 ;
     RECT  26.676 12.427 30.546 12.479 ;
     RECT  2.304 11.851 2.697 12.595 ;
     RECT  3.492 12.361 3.834 12.595 ;
     RECT  4.788 12.451 4.95 12.595 ;
     RECT  2.304 12.595 4.95 12.757 ;
     RECT  5.796 11.705 5.85 12.757 ;
     RECT  2.304 12.757 5.85 12.785 ;
     RECT  13.215 2.413 13.497 12.865 ;
     RECT  14.436 12.763 14.454 12.865 ;
     RECT  2.415 12.785 5.85 12.901 ;
     RECT  27.936 12.479 30.546 12.941 ;
     RECT  13.215 12.865 14.454 12.991 ;
     RECT  13.104 12.991 14.454 13.019 ;
     RECT  13.104 13.019 14.13 13.037 ;
     RECT  2.415 12.901 6.318 13.055 ;
     RECT  13.215 13.037 14.13 13.133 ;
     RECT  4.788 13.055 6.318 13.171 ;
     RECT  7.56 12.269 8.097 13.171 ;
     RECT  0.108 13.027 0.126 13.181 ;
     RECT  13.215 13.133 13.662 13.289 ;
     RECT  4.788 13.171 8.097 13.361 ;
     RECT  4.788 13.361 6.318 13.469 ;
     RECT  7.272 13.361 8.097 13.595 ;
     RECT  9.036 12.209 9.306 13.639 ;
     RECT  13.215 13.289 13.554 13.661 ;
     RECT  9.036 13.639 9.594 13.675 ;
     RECT  8.928 13.675 9.594 13.829 ;
     RECT  2.415 13.055 3.834 14.011 ;
     RECT  4.788 13.469 4.95 14.071 ;
     RECT  2.304 14.011 3.834 14.215 ;
     RECT  4.752 14.071 4.95 14.215 ;
     RECT  2.304 14.215 4.95 14.405 ;
     RECT  2.304 14.405 2.697 14.675 ;
     RECT  5.796 13.469 6.318 14.755 ;
     RECT  5.688 14.755 6.318 14.881 ;
     RECT  5.688 14.881 6.498 14.909 ;
     RECT  7.56 13.595 8.097 14.917 ;
     RECT  2.412 14.675 2.697 14.945 ;
     RECT  3.816 14.405 4.95 14.945 ;
     RECT  5.796 14.909 6.498 15.061 ;
     RECT  7.272 14.917 8.097 15.061 ;
     RECT  5.796 15.061 8.097 15.179 ;
     RECT  7.272 15.179 8.097 15.215 ;
     RECT  2.415 14.945 2.697 15.295 ;
     RECT  3.816 14.945 3.906 15.331 ;
     RECT  7.416 15.215 8.097 15.403 ;
     RECT  7.416 15.403 8.19 15.421 ;
     RECT  7.416 15.421 8.262 15.457 ;
     RECT  9.036 13.829 9.594 15.457 ;
     RECT  7.416 15.457 9.594 15.533 ;
     RECT  2.415 15.295 2.826 15.727 ;
     RECT  8.892 15.533 9.594 15.755 ;
     RECT  2.304 15.727 2.826 15.829 ;
     RECT  3.744 15.331 3.906 15.829 ;
     RECT  2.304 15.829 3.906 15.835 ;
     RECT  4.752 14.945 4.95 15.835 ;
     RECT  2.304 15.835 4.95 16.025 ;
     RECT  2.304 16.025 2.898 16.295 ;
     RECT  3.816 16.025 4.95 16.375 ;
     RECT  5.796 15.179 6.318 16.375 ;
     RECT  3.816 16.375 6.318 16.507 ;
     RECT  3.816 16.507 6.462 16.529 ;
     RECT  2.415 16.295 2.898 16.799 ;
     RECT  7.416 15.533 8.097 16.843 ;
     RECT  7.416 16.843 8.154 16.915 ;
     RECT  5.832 16.529 6.462 16.951 ;
     RECT  7.308 16.915 8.154 16.951 ;
     RECT  2.415 16.799 2.697 17.035 ;
     RECT  5.832 16.951 8.154 17.069 ;
     RECT  9 15.755 9.594 17.077 ;
     RECT  2.304 17.035 2.697 17.105 ;
     RECT  8.892 17.077 9.594 17.375 ;
     RECT  2.415 17.105 2.697 17.611 ;
     RECT  3.816 16.529 4.95 17.611 ;
     RECT  2.415 17.611 4.95 17.899 ;
     RECT  2.412 17.899 4.95 17.915 ;
     RECT  3.816 17.915 4.95 17.923 ;
     RECT  3.816 17.923 4.986 18.265 ;
     RECT  5.832 17.069 8.097 18.265 ;
     RECT  2.412 17.915 2.697 18.331 ;
     RECT  9 17.375 9.594 18.427 ;
     RECT  2.304 18.331 2.697 18.455 ;
     RECT  3.816 18.265 8.097 18.571 ;
     RECT  3.816 18.571 8.226 18.761 ;
     RECT  7.452 18.761 8.226 18.805 ;
     RECT  8.964 18.427 9.594 18.805 ;
     RECT  5.796 18.761 6.462 18.845 ;
     RECT  2.415 18.455 2.697 19.195 ;
     RECT  3.816 18.761 4.986 19.195 ;
     RECT  2.304 19.195 4.986 19.535 ;
     RECT  7.452 18.805 9.594 19.709 ;
     RECT  7.452 19.709 8.097 19.741 ;
     RECT  3.816 19.535 4.986 19.777 ;
     RECT  5.796 18.845 6.318 19.777 ;
     RECT  3.816 19.777 6.318 19.963 ;
     RECT  7.416 19.741 8.097 20.191 ;
     RECT  3.816 19.963 6.462 20.345 ;
     RECT  7.308 20.191 8.097 20.345 ;
     RECT  3.816 20.345 6.318 20.615 ;
     RECT  8.856 19.709 9.594 20.695 ;
     RECT  7.416 20.345 8.097 20.731 ;
     RECT  8.82 20.695 9.594 20.731 ;
     RECT  3.816 20.615 4.986 20.779 ;
     RECT  3.456 20.779 4.986 20.893 ;
     RECT  7.416 20.731 9.594 20.909 ;
     RECT  3.42 20.893 4.986 21.155 ;
     RECT  3.816 21.155 4.986 21.397 ;
     RECT  5.796 20.615 6.318 21.397 ;
     RECT  2.304 19.535 2.697 21.425 ;
     RECT  3.816 21.397 6.318 21.631 ;
     RECT  7.416 20.909 8.097 21.631 ;
     RECT  7.308 21.631 8.097 21.775 ;
     RECT  3.816 21.631 6.354 21.869 ;
     RECT  7.2 21.775 8.097 21.929 ;
     RECT  0.54 22.207 0.558 22.253 ;
     RECT  8.856 20.909 9.594 22.315 ;
     RECT  3.816 21.869 6.318 22.505 ;
     RECT  8.82 22.315 9.594 22.649 ;
     RECT  2.415 21.425 2.697 22.651 ;
     RECT  2.304 22.651 2.697 22.795 ;
     RECT  3.816 22.505 4.986 22.795 ;
     RECT  8.82 22.649 9.522 23.021 ;
     RECT  7.596 21.929 8.097 23.053 ;
     RECT  2.304 22.795 4.986 23.153 ;
     RECT  2.415 23.153 4.986 23.395 ;
     RECT  5.76 22.505 6.318 23.395 ;
     RECT  7.524 23.053 8.097 23.665 ;
     RECT  2.415 23.395 6.318 23.701 ;
     RECT  7.2 23.665 8.097 23.701 ;
     RECT  8.82 23.021 9.486 23.701 ;
     RECT  2.415 23.701 9.486 23.927 ;
     RECT  2.415 23.927 6.318 23.947 ;
     RECT  7.2 23.927 9.486 23.963 ;
     RECT  48.996 23.899 49.23 24.061 ;
     RECT  50.688 24.133 50.706 24.173 ;
     RECT  47.988 24.241 48.006 24.359 ;
     RECT  45.615 2.413 45.897 24.469 ;
     RECT  26.676 12.479 27.09 24.475 ;
     RECT  27.936 12.941 27.954 24.475 ;
     RECT  7.524 23.963 9.486 24.629 ;
     RECT  2.304 23.947 6.318 24.665 ;
     RECT  45.615 24.469 46.53 24.673 ;
     RECT  28.764 12.941 30.546 24.871 ;
     RECT  45.504 24.673 46.53 25.003 ;
     RECT  44.964 25.003 46.53 25.015 ;
     RECT  44.424 25.015 46.53 25.051 ;
     RECT  47.304 24.439 47.394 25.051 ;
     RECT  48.132 24.745 48.15 25.141 ;
     RECT  48.996 24.061 49.338 25.141 ;
     RECT  3.42 24.665 6.318 25.169 ;
     RECT  3.42 25.169 4.986 25.205 ;
     RECT  44.424 25.051 47.394 25.205 ;
     RECT  48.132 25.141 49.338 25.285 ;
     RECT  5.76 25.169 6.318 25.321 ;
     RECT  7.524 24.629 9.342 25.321 ;
     RECT  26.676 24.475 27.954 25.321 ;
     RECT  28.728 24.871 30.546 25.321 ;
     RECT  44.424 25.205 45.897 25.321 ;
     RECT  46.764 25.205 47.394 25.321 ;
     RECT  48.132 25.285 49.374 25.321 ;
     RECT  50.724 24.475 50.742 25.435 ;
     RECT  2.304 24.665 2.697 25.475 ;
     RECT  5.76 25.321 9.342 25.547 ;
     RECT  38.772 25.411 38.79 25.547 ;
     RECT  42.912 25.249 42.93 25.555 ;
     RECT  44.1 25.321 45.897 25.579 ;
     RECT  43.956 25.579 45.897 25.583 ;
     RECT  42.372 25.555 43.182 25.591 ;
     RECT  43.956 25.583 44.442 25.591 ;
     RECT  42.372 25.591 44.442 25.613 ;
     RECT  42.912 25.613 43.974 25.619 ;
     RECT  7.308 25.547 9.342 25.709 ;
     RECT  42.912 25.619 43.902 25.709 ;
     RECT  45.288 25.583 45.897 25.709 ;
     RECT  2.412 25.475 2.697 25.745 ;
     RECT  43.884 25.709 43.902 25.745 ;
     RECT  50.688 25.435 50.742 25.901 ;
     RECT  46.764 25.321 49.374 25.979 ;
     RECT  45.504 25.709 45.897 26.011 ;
     RECT  46.764 25.979 49.338 26.011 ;
     RECT  34.02 25.951 34.038 26.249 ;
     RECT  2.415 25.745 2.697 26.251 ;
     RECT  3.744 25.205 4.986 26.251 ;
     RECT  5.76 25.547 6.462 26.365 ;
     RECT  5.76 26.365 6.498 26.401 ;
     RECT  2.415 26.251 4.986 26.527 ;
     RECT  45.504 26.011 49.338 26.555 ;
     RECT  2.304 26.527 4.986 26.635 ;
     RECT  5.76 26.401 6.786 26.635 ;
     RECT  34.815 2.413 35.097 26.671 ;
     RECT  50.688 25.901 50.706 26.731 ;
     RECT  33.084 26.401 33.102 26.761 ;
     RECT  34.776 26.671 35.097 26.789 ;
     RECT  50.652 26.731 50.706 26.789 ;
     RECT  45.504 26.555 48.474 27.059 ;
     RECT  48.348 27.059 48.474 27.131 ;
     RECT  2.304 26.635 6.786 27.139 ;
     RECT  7.524 25.709 9.342 27.139 ;
     RECT  42.912 25.709 42.93 27.139 ;
     RECT  50.652 26.789 50.67 27.163 ;
     RECT  45.504 27.059 47.394 27.167 ;
     RECT  44.748 26.905 44.766 27.203 ;
     RECT  42.768 27.139 43.326 27.205 ;
     RECT  33.012 26.761 33.102 27.211 ;
     RECT  45.504 27.167 45.897 27.211 ;
     RECT  33.012 27.211 33.354 27.301 ;
     RECT  42.768 27.205 43.974 27.307 ;
     RECT  45.288 27.211 45.897 27.329 ;
     RECT  42.372 27.307 43.974 27.341 ;
     RECT  42.372 27.341 43.326 27.365 ;
     RECT  33.012 27.301 34.002 27.373 ;
     RECT  42.768 27.365 43.326 27.401 ;
     RECT  48.456 27.131 48.474 27.571 ;
     RECT  49.32 26.555 49.338 27.571 ;
     RECT  50.616 27.163 50.67 27.595 ;
     RECT  32.472 27.373 34.002 27.599 ;
     RECT  42.768 27.401 43.146 27.635 ;
     RECT  2.304 27.139 9.342 27.715 ;
     RECT  10.584 27.211 10.602 27.715 ;
     RECT  48.456 27.571 49.338 27.751 ;
     RECT  2.304 27.715 10.602 27.877 ;
     RECT  2.304 27.877 10.782 27.905 ;
     RECT  42.768 27.635 42.786 27.905 ;
     RECT  46.62 27.167 47.394 27.905 ;
     RECT  47.376 27.905 47.394 27.941 ;
     RECT  11.772 27.715 11.79 28.013 ;
     RECT  48.456 27.751 49.374 28.021 ;
     RECT  50.616 27.595 50.706 28.139 ;
     RECT  47.916 28.021 49.374 28.175 ;
     RECT  50.688 28.139 50.706 28.409 ;
     RECT  2.415 27.905 10.782 28.445 ;
     RECT  48.996 28.175 49.014 28.445 ;
     RECT  3.78 28.445 10.782 28.493 ;
     RECT  3.78 28.493 9.27 28.715 ;
     RECT  3.78 28.715 5.058 28.985 ;
     RECT  2.415 28.445 2.697 29.131 ;
     RECT  2.304 29.131 2.697 29.255 ;
     RECT  5.832 28.715 9.27 29.461 ;
     RECT  4.104 28.985 5.058 29.911 ;
     RECT  2.415 29.255 2.697 29.992 ;
     RECT  3.492 29.911 5.058 29.992 ;
     RECT  2.415 29.992 5.058 29.995 ;
     RECT  2.34 29.995 5.058 30.037 ;
     RECT  5.832 29.461 9.378 30.037 ;
     RECT  2.34 30.037 9.378 30.065 ;
     RECT  11.52 30.145 11.538 30.299 ;
     RECT  2.415 30.065 9.378 30.335 ;
     RECT  4.212 30.335 9.378 30.379 ;
     RECT  10.584 28.493 10.782 30.379 ;
     RECT  10.584 30.379 11.214 30.415 ;
     RECT  4.212 30.379 9.45 30.451 ;
     RECT  10.224 30.415 11.214 30.451 ;
     RECT  4.212 30.451 11.214 30.569 ;
     RECT  4.212 30.569 5.022 30.605 ;
     RECT  5.832 30.569 11.214 30.749 ;
     RECT  10.224 30.749 11.214 30.839 ;
     RECT  19.62 30.541 19.638 30.991 ;
     RECT  11.988 30.919 12.006 31.109 ;
     RECT  10.584 30.839 11.214 31.117 ;
     RECT  2.415 30.335 3.222 31.291 ;
     RECT  10.584 31.117 11.502 31.415 ;
     RECT  2.304 31.291 3.222 31.495 ;
     RECT  4.212 30.605 4.914 31.495 ;
     RECT  2.304 31.495 3.294 31.531 ;
     RECT  4.104 31.495 4.914 31.531 ;
     RECT  2.304 31.531 4.914 31.657 ;
     RECT  5.832 30.749 9.378 31.657 ;
     RECT  18.615 2.413 18.897 31.801 ;
     RECT  19.62 30.991 20.106 31.801 ;
     RECT  2.304 31.657 9.378 31.919 ;
     RECT  32.472 27.599 33.894 31.919 ;
     RECT  2.304 31.919 3.15 31.955 ;
     RECT  4.14 31.919 9.378 31.955 ;
     RECT  4.212 31.955 9.378 32.071 ;
     RECT  4.212 32.071 9.414 32.225 ;
     RECT  4.212 32.225 9.378 32.495 ;
     RECT  10.584 31.415 10.782 32.999 ;
     RECT  2.304 31.955 2.697 33.115 ;
     RECT  4.212 32.495 4.914 33.115 ;
     RECT  2.304 33.115 3.33 33.151 ;
     RECT  4.104 33.115 4.914 33.151 ;
     RECT  2.304 33.151 4.914 33.269 ;
     RECT  10.584 32.999 10.602 33.269 ;
     RECT  5.76 32.495 9.378 33.277 ;
     RECT  4.212 33.269 4.914 33.511 ;
     RECT  5.76 33.277 10.098 33.575 ;
     RECT  18.615 31.801 20.106 33.583 ;
     RECT  4.212 33.511 5.022 33.619 ;
     RECT  5.76 33.575 9.738 33.619 ;
     RECT  2.304 33.269 3.33 34.385 ;
     RECT  33.876 31.919 33.894 34.619 ;
     RECT  4.212 33.619 9.738 34.735 ;
     RECT  32.472 31.919 33.102 34.735 ;
     RECT  2.415 34.385 3.33 34.771 ;
     RECT  4.176 34.735 9.738 34.771 ;
     RECT  2.415 34.771 9.738 34.889 ;
     RECT  6.12 34.889 9.738 35.159 ;
     RECT  2.415 34.889 5.31 35.195 ;
     RECT  2.415 35.195 3.51 35.213 ;
     RECT  2.415 35.213 2.697 35.611 ;
     RECT  3.492 35.213 3.51 35.699 ;
     RECT  2.304 35.611 2.697 35.735 ;
     RECT  6.12 35.159 9.558 35.735 ;
     RECT  32.472 34.735 33.426 36.085 ;
     RECT  4.5 35.195 5.13 36.121 ;
     RECT  26.676 25.321 30.546 36.391 ;
     RECT  31.356 36.235 31.518 36.391 ;
     RECT  2.415 35.735 2.697 36.475 ;
     RECT  2.304 36.475 2.697 36.517 ;
     RECT  3.78 36.121 5.13 36.517 ;
     RECT  26.676 36.391 31.518 36.517 ;
     RECT  32.364 36.085 33.426 36.517 ;
     RECT  2.304 36.517 5.13 36.545 ;
     RECT  26.676 36.517 33.426 36.581 ;
     RECT  2.415 36.545 5.13 36.859 ;
     RECT  2.415 36.859 5.346 36.895 ;
     RECT  6.12 35.735 6.354 36.895 ;
     RECT  27.54 36.581 33.426 37.049 ;
     RECT  26.676 36.581 26.802 37.165 ;
     RECT  24.015 10.882 25.362 37.201 ;
     RECT  7.092 35.735 9.558 37.291 ;
     RECT  2.415 36.895 6.354 37.429 ;
     RECT  7.092 37.291 9.702 37.429 ;
     RECT  24.015 37.201 25.686 37.471 ;
     RECT  26.532 37.165 26.802 37.471 ;
     RECT  27.54 37.049 31.626 37.471 ;
     RECT  2.415 37.429 9.702 37.589 ;
     RECT  2.415 37.589 6.642 37.625 ;
     RECT  24.015 37.471 31.626 37.625 ;
     RECT  24.015 37.625 31.266 37.661 ;
     RECT  2.415 37.625 4.554 37.771 ;
     RECT  24.015 37.661 31.122 37.859 ;
     RECT  2.304 37.771 4.554 37.895 ;
     RECT  32.4 37.049 33.426 37.939 ;
     RECT  24.015 37.859 31.014 37.967 ;
     RECT  24.015 37.967 30.87 38.129 ;
     RECT  24.015 38.129 30.798 38.201 ;
     RECT  0.108 38.137 0.126 38.237 ;
     RECT  2.415 37.895 4.554 38.399 ;
     RECT  7.815 37.589 9.702 38.399 ;
     RECT  2.415 38.399 3.15 38.435 ;
     RECT  3.996 38.399 4.554 38.435 ;
     RECT  2.415 38.435 2.697 38.635 ;
     RECT  4.356 38.435 4.554 38.635 ;
     RECT  5.328 37.625 6.138 38.635 ;
     RECT  32.4 37.939 34.074 38.635 ;
     RECT  24.015 38.201 30.726 38.749 ;
     RECT  31.932 38.635 34.074 38.779 ;
     RECT  23.976 38.749 30.726 38.813 ;
     RECT  31.716 38.779 34.074 38.813 ;
     RECT  4.356 38.635 6.138 38.939 ;
     RECT  4.356 38.939 4.374 38.975 ;
     RECT  25.668 38.813 30.726 39.019 ;
     RECT  7.815 38.399 9.558 39.091 ;
     RECT  5.22 38.939 6.138 39.181 ;
     RECT  5.22 39.181 6.246 39.211 ;
     RECT  7.416 39.091 9.558 39.217 ;
     RECT  5.22 39.211 6.462 39.251 ;
     RECT  25.668 39.019 30.942 39.361 ;
     RECT  31.716 38.813 31.734 39.361 ;
     RECT  32.472 38.813 34.074 39.361 ;
     RECT  34.815 26.789 35.097 39.361 ;
     RECT  5.22 39.251 6.246 39.479 ;
     RECT  32.472 39.361 35.097 39.479 ;
     RECT  2.304 38.635 2.697 39.487 ;
     RECT  5.22 39.479 5.706 39.515 ;
     RECT  25.668 39.361 31.734 39.551 ;
     RECT  32.472 39.479 34.074 39.631 ;
     RECT  23.976 38.813 24.678 39.883 ;
     RECT  25.668 39.551 31.158 39.883 ;
     RECT  3.96 39.631 3.978 39.901 ;
     RECT  7.272 39.217 9.558 40.027 ;
     RECT  23.976 39.883 31.158 40.127 ;
     RECT  2.304 39.487 2.826 40.135 ;
     RECT  3.96 39.901 4.23 40.135 ;
     RECT  2.304 40.135 4.23 40.267 ;
     RECT  5.688 39.515 5.706 40.297 ;
     RECT  2.304 40.267 4.806 40.325 ;
     RECT  2.304 40.325 4.158 40.433 ;
     RECT  5.652 40.297 5.706 40.441 ;
     RECT  6.84 40.027 9.558 40.555 ;
     RECT  2.415 40.433 4.158 40.559 ;
     RECT  4.932 40.441 5.706 40.559 ;
     RECT  16.164 34.591 16.182 40.559 ;
     RECT  4.14 40.559 4.158 40.595 ;
     RECT  31.896 39.631 34.074 40.801 ;
     RECT  5.148 40.559 5.706 40.829 ;
     RECT  6.48 40.555 9.558 40.829 ;
     RECT  23.976 40.127 30.942 40.837 ;
     RECT  23.544 40.837 30.942 40.909 ;
     RECT  31.788 40.801 34.074 40.909 ;
     RECT  6.48 40.829 9.378 40.981 ;
     RECT  6.228 40.981 9.378 41.099 ;
     RECT  5.148 40.829 5.166 41.135 ;
     RECT  23.544 40.909 34.074 41.143 ;
     RECT  2.415 40.559 3.402 41.227 ;
     RECT  6.84 41.099 8.838 41.369 ;
     RECT  22.824 41.143 34.074 41.369 ;
     RECT  2.412 41.227 3.402 41.405 ;
     RECT  32.472 41.369 34.074 41.405 ;
     RECT  32.58 41.405 34.074 41.513 ;
     RECT  22.824 41.369 31.662 41.549 ;
     RECT  23.544 41.549 31.662 41.639 ;
     RECT  27.576 41.639 31.662 41.675 ;
     RECT  18.615 33.583 20.286 42.235 ;
     RECT  22.536 42.379 22.554 42.449 ;
     RECT  18.615 42.235 20.97 42.667 ;
     RECT  23.544 41.639 26.586 42.691 ;
     RECT  18.615 42.667 21.006 42.719 ;
     RECT  7.308 41.369 8.097 42.755 ;
     RECT  27.648 41.675 31.662 42.763 ;
     RECT  32.688 41.513 34.074 42.799 ;
     RECT  23.328 42.691 26.586 42.827 ;
     RECT  27.36 42.763 31.662 42.871 ;
     RECT  32.508 42.799 34.074 42.871 ;
     RECT  7.38 42.755 8.097 42.989 ;
     RECT  27.36 42.871 34.074 43.061 ;
     RECT  23.328 42.827 26.298 43.259 ;
     RECT  27.36 43.061 31.842 43.951 ;
     RECT  23.328 43.259 26.262 44.077 ;
     RECT  27.036 43.951 31.842 44.077 ;
     RECT  18.615 42.719 20.286 44.443 ;
     RECT  23.328 44.077 31.842 44.491 ;
     RECT  22.788 44.491 31.842 44.689 ;
     RECT  22.428 44.689 31.842 44.851 ;
     RECT  32.58 43.061 34.074 44.851 ;
     RECT  18.072 44.443 20.286 44.879 ;
     RECT  22.428 44.851 34.074 45.023 ;
     RECT  14.724 43.105 14.742 45.059 ;
     RECT  17.1 45.031 17.118 45.221 ;
     RECT  22.428 45.023 26.514 45.301 ;
     RECT  27.252 45.023 34.074 45.329 ;
     RECT  33.228 45.329 34.074 45.419 ;
     RECT  27.252 45.329 32.202 45.527 ;
     RECT  27.252 45.527 32.058 45.563 ;
     RECT  22.284 45.301 26.514 45.571 ;
     RECT  21.096 45.691 21.114 45.731 ;
     RECT  21.924 45.571 26.514 45.733 ;
     RECT  21.276 45.733 26.514 45.841 ;
     RECT  27.252 45.563 31.41 45.841 ;
     RECT  21.276 45.841 31.41 45.959 ;
     RECT  21.276 45.959 31.266 46.337 ;
     RECT  27.324 46.337 31.266 46.397 ;
     RECT  8.82 41.369 8.838 46.499 ;
     RECT  15.948 40.675 15.966 46.643 ;
     RECT  21.276 46.337 26.55 46.777 ;
     RECT  21.204 46.777 26.55 46.849 ;
     RECT  18.615 44.879 20.286 46.885 ;
     RECT  21.132 46.849 26.55 46.885 ;
     RECT  16.704 46.543 16.722 47.191 ;
     RECT  18.615 46.885 26.55 47.281 ;
     RECT  18.36 47.281 26.55 47.317 ;
     RECT  27.36 46.397 31.266 47.317 ;
     RECT  32.724 46.921 32.742 47.353 ;
     RECT  18.36 47.317 31.266 47.371 ;
     RECT  18.36 47.371 31.482 47.425 ;
     RECT  17.964 47.425 31.482 47.461 ;
     RECT  33.66 45.419 34.074 47.461 ;
     RECT  34.815 39.479 35.097 47.551 ;
     RECT  35.82 47.389 35.838 47.551 ;
     RECT  34.815 47.551 35.838 47.587 ;
     RECT  17.712 47.461 31.482 47.623 ;
     RECT  32.328 47.353 32.742 47.623 ;
     RECT  17.712 47.623 32.742 47.695 ;
     RECT  16.704 47.191 16.902 47.731 ;
     RECT  17.712 47.695 32.814 47.731 ;
     RECT  33.624 47.461 34.074 47.731 ;
     RECT  34.815 47.587 36.162 47.821 ;
     RECT  36.936 47.551 36.954 47.821 ;
     RECT  16.704 47.731 34.074 47.857 ;
     RECT  34.815 47.821 36.954 47.857 ;
     RECT  16.704 47.857 36.954 48.001 ;
     RECT  16.704 48.001 37.134 48.227 ;
     RECT  15.804 48.199 15.822 48.235 ;
     RECT  16.704 48.227 19.674 48.235 ;
     RECT  20.52 48.227 37.134 48.263 ;
     RECT  20.52 48.263 36.954 48.659 ;
     RECT  14.364 48.427 14.382 48.811 ;
     RECT  14.364 48.811 14.526 48.929 ;
     RECT  15.264 48.235 19.674 49.001 ;
     RECT  15.66 49.001 19.674 49.045 ;
     RECT  20.52 48.659 36.81 49.045 ;
     RECT  15.66 49.045 36.81 49.199 ;
     RECT  2.415 41.405 2.697 49.427 ;
     RECT  7.815 42.989 8.097 49.427 ;
     RECT  13.215 13.661 13.497 49.427 ;
     RECT  40.215 2.413 40.497 49.427 ;
     RECT  45.615 27.329 45.897 49.427 ;
     RECT  15.696 49.199 36.594 49.469 ;
     RECT  15.804 49.469 28.134 49.505 ;
     RECT  15.948 49.505 28.134 49.517 ;
     RECT  29.196 49.469 36.486 49.517 ;
     RECT  16.92 49.517 26.082 49.565 ;
     RECT  26.856 49.517 28.134 49.565 ;
     RECT  29.415 49.517 30.834 49.565 ;
     RECT  33.768 49.517 36.486 49.565 ;
     RECT  15.948 49.517 16.074 49.577 ;
     RECT  16.92 49.565 25.686 49.577 ;
     RECT  26.856 49.565 26.874 49.577 ;
     RECT  30.312 49.565 30.33 49.577 ;
     RECT  31.824 49.517 32.922 49.577 ;
     RECT  33.768 49.565 34.905 49.577 ;
     RECT  35.928 49.565 36.486 49.577 ;
     RECT  2.415 49.427 2.505 49.697 ;
     RECT  7.815 49.427 7.905 49.697 ;
     RECT  13.215 49.427 13.305 49.697 ;
     RECT  23.832 49.577 24.105 49.697 ;
     RECT  29.415 49.565 29.574 49.697 ;
     RECT  34.74 49.577 34.905 49.697 ;
     RECT  40.215 49.427 40.305 49.697 ;
     RECT  45.615 49.427 45.705 49.697 ;
     RECT  18.216 49.577 18.774 49.805 ;
     RECT  29.556 49.697 29.574 49.805 ;
     RECT  34.74 49.697 34.758 49.853 ;
     RECT  18.216 49.805 18.234 50.765 ;
     RECT  22.104 49.577 22.122 50.765 ;
     RECT  23.832 49.697 23.85 50.765 ;
     RECT  32.472 49.577 32.49 50.765 ;
     RECT  36.468 49.577 36.486 50.765 ;
    LAYER M4 ;
     RECT  0.06 10.56 2.408 41.256 ;
     RECT  2.408 2.148 2.512 49.692 ;
     RECT  2.512 2.418 2.704 49.422 ;
     RECT  2.704 15.312 2.837 15.864 ;
     RECT  2.704 27.936 2.837 28.296 ;
     RECT  2.704 30 2.837 31.656 ;
     RECT  2.704 35.184 2.837 35.208 ;
     RECT  2.704 36.912 2.837 37.368 ;
     RECT  2.704 39.504 2.837 40.296 ;
     RECT  2.837 15.408 3.347 15.864 ;
     RECT  2.704 17.616 3.347 17.64 ;
     RECT  2.704 18.816 3.347 19.224 ;
     RECT  2.704 10.8 3.349 11.448 ;
     RECT  2.704 12.768 3.733 13.608 ;
     RECT  2.704 26.256 3.733 26.28 ;
     RECT  2.704 22.8 4.021 22.824 ;
     RECT  2.704 20.784 4.549 20.808 ;
     RECT  4.021 21.936 4.549 22.824 ;
     RECT  4.549 19.92 4.595 22.824 ;
     RECT  2.837 31.632 4.637 31.656 ;
     RECT  2.837 30 4.705 30.024 ;
     RECT  3.733 12.768 4.789 13.704 ;
     RECT  3.347 15.408 4.789 15.432 ;
     RECT  2.837 36.912 4.789 36.936 ;
     RECT  3.733 26.208 4.796 26.28 ;
     RECT  3.349 11.424 4.813 11.448 ;
     RECT  2.837 27.936 4.813 27.96 ;
     RECT  4.705 29.088 4.813 30.024 ;
     RECT  4.796 26.208 4.837 26.568 ;
     RECT  4.813 27.936 4.837 30.024 ;
     RECT  4.789 12.768 4.853 15.432 ;
     RECT  4.595 21.36 4.853 22.824 ;
     RECT  4.853 13.296 4.876 15.432 ;
     RECT  4.789 38.64 4.876 39.24 ;
     RECT  4.789 36.912 4.881 37.464 ;
     RECT  2.837 40.272 4.881 40.296 ;
     RECT  3.347 18.816 4.889 18.84 ;
     RECT  4.595 19.92 4.889 19.944 ;
     RECT  4.805 25.056 4.889 25.08 ;
     RECT  4.837 26.208 4.889 30.024 ;
     RECT  4.853 21.84 4.979 22.824 ;
     RECT  4.889 26.208 5.027 29.112 ;
     RECT  4.979 21.84 5.075 21.96 ;
     RECT  4.813 11.376 5.177 11.448 ;
     RECT  5.075 21.84 5.893 21.864 ;
     RECT  4.876 13.296 6.005 13.704 ;
     RECT  4.876 15.408 6.145 15.432 ;
     RECT  5.027 26.208 6.217 28.824 ;
     RECT  2.704 33.6 6.277 33.624 ;
     RECT  6.145 35.328 6.277 35.352 ;
     RECT  6.277 33.6 6.323 35.352 ;
     RECT  5.893 21.648 6.365 21.864 ;
     RECT  4.849 16.512 6.369 16.536 ;
     RECT  5.029 19.632 6.389 19.656 ;
     RECT  6.389 19.632 6.421 19.992 ;
     RECT  5.177 11.376 6.433 11.4 ;
     RECT  6.217 26.112 6.433 28.824 ;
     RECT  6.323 33.6 6.437 34.776 ;
     RECT  6.145 15.408 6.469 15.528 ;
     RECT  6.433 11.376 6.473 11.496 ;
     RECT  6.369 16.512 6.473 16.872 ;
     RECT  6.421 18.432 6.473 19.992 ;
     RECT  6.433 26.112 6.473 29.592 ;
     RECT  4.881 37.44 6.473 37.464 ;
     RECT  6.473 18.432 6.508 19.656 ;
     RECT  6.473 27.312 6.545 28.488 ;
     RECT  6.437 34.368 6.761 34.776 ;
     RECT  4.876 39.216 7.388 39.24 ;
     RECT  6.469 40.56 7.388 40.584 ;
     RECT  7.153 31.68 7.621 31.704 ;
     RECT  6.005 13.296 7.669 13.56 ;
     RECT  6.473 11.472 7.808 11.496 ;
     RECT  7.669 13.296 7.808 13.608 ;
     RECT  6.469 14.928 7.808 15.528 ;
     RECT  6.473 16.848 7.808 16.872 ;
     RECT  6.508 18.816 7.808 19.656 ;
     RECT  7.669 23.664 7.808 23.688 ;
     RECT  6.473 26.112 7.808 26.136 ;
     RECT  6.545 27.888 7.808 28.488 ;
     RECT  6.473 29.568 7.808 29.592 ;
     RECT  7.621 30.96 7.808 31.704 ;
     RECT  6.757 33.072 7.808 33.096 ;
     RECT  6.761 34.368 7.808 34.68 ;
     RECT  7.669 37.968 7.808 37.992 ;
     RECT  7.388 39.216 7.808 40.584 ;
     RECT  7.808 2.148 7.912 49.692 ;
     RECT  7.912 2.418 8.104 49.422 ;
     RECT  8.104 16.848 8.165 16.872 ;
     RECT  8.104 26.112 8.165 26.232 ;
     RECT  8.104 11.472 8.243 13.656 ;
     RECT  8.104 14.928 8.243 15.528 ;
     RECT  8.104 19.248 8.243 19.704 ;
     RECT  8.104 20.88 8.243 20.904 ;
     RECT  8.104 22.224 8.243 23.064 ;
     RECT  8.104 27.696 8.243 29.352 ;
     RECT  8.104 30.432 8.243 32.04 ;
     RECT  8.104 34.368 8.243 36.12 ;
     RECT  8.243 15.408 8.245 15.528 ;
     RECT  8.165 26.208 8.245 26.232 ;
     RECT  8.245 15.504 8.273 15.528 ;
     RECT  8.243 27.888 8.273 29.352 ;
     RECT  8.243 30.432 8.381 30.984 ;
     RECT  8.243 34.368 8.483 35.304 ;
     RECT  8.483 35.28 8.489 35.304 ;
     RECT  8.243 19.68 8.597 19.704 ;
     RECT  8.273 27.936 8.921 29.352 ;
     RECT  8.104 38.16 9.164 38.184 ;
     RECT  8.243 22.992 9.245 23.064 ;
     RECT  9.164 37.584 9.251 38.184 ;
     RECT  8.104 33.072 9.353 33.096 ;
     RECT  8.381 30.432 9.461 30.696 ;
     RECT  9.245 22.992 9.533 23.016 ;
     RECT  9.461 30.432 9.569 30.504 ;
     RECT  9.251 38.16 9.713 38.184 ;
     RECT  8.921 27.936 9.857 28.488 ;
     RECT  9.857 28.176 9.929 28.488 ;
     RECT  9.569 30.432 10.253 30.456 ;
     RECT  8.243 13.008 13.208 13.656 ;
     RECT  9.929 28.176 13.208 28.2 ;
     RECT  13.208 2.148 13.312 49.692 ;
     RECT  13.312 2.418 13.504 49.422 ;
     RECT  13.504 12.768 13.565 13.656 ;
     RECT  13.504 48.432 15.733 48.456 ;
     RECT  15.733 48.432 15.82 49.032 ;
     RECT  16.045 49.488 16.697 49.56 ;
     RECT  15.82 48.432 17.125 48.456 ;
     RECT  18.205 50.736 18.371 50.76 ;
     RECT  13.565 12.768 18.608 13.128 ;
     RECT  15.301 26.304 18.608 26.328 ;
     RECT  13.504 28.176 18.608 28.2 ;
     RECT  18.085 42.48 18.608 42.504 ;
     RECT  18.061 44.448 18.608 44.472 ;
     RECT  17.125 48.192 18.608 48.456 ;
     RECT  16.697 49.536 18.608 49.56 ;
     RECT  18.608 2.148 18.712 49.692 ;
     RECT  18.712 2.418 18.716 49.692 ;
     RECT  18.716 2.418 18.803 49.8 ;
     RECT  18.803 2.418 18.904 49.56 ;
     RECT  18.904 45.312 19.187 45.336 ;
     RECT  18.904 47.136 19.577 48.456 ;
     RECT  18.904 42.48 20.941 42.504 ;
     RECT  20.941 42.24 20.977 42.504 ;
     RECT  19.577 47.136 20.977 47.88 ;
     RECT  20.977 47.088 21.109 47.88 ;
     RECT  20.977 42.24 21.155 42.696 ;
     RECT  21.068 45.696 21.155 45.72 ;
     RECT  21.109 47.088 21.155 48.504 ;
     RECT  21.155 48.48 21.557 48.504 ;
     RECT  21.155 47.088 22.201 47.352 ;
     RECT  22.093 50.736 22.259 50.76 ;
     RECT  18.904 12.768 22.499 13.128 ;
     RECT  21.155 42.24 22.595 42.408 ;
     RECT  22.201 47.088 22.68 47.4 ;
     RECT  22.453 3.696 22.7 3.72 ;
     RECT  22.68 47.088 22.741 47.592 ;
     RECT  22.7 2.832 22.787 3.72 ;
     RECT  22.741 47.088 22.811 48.264 ;
     RECT  22.787 3.696 23.605 3.72 ;
     RECT  23.821 50.736 23.987 50.76 ;
     RECT  22.417 1.728 24.008 1.752 ;
     RECT  23.605 3.696 24.008 3.96 ;
     RECT  22.499 13.104 24.008 13.128 ;
     RECT  18.904 26.304 24.008 26.328 ;
     RECT  18.904 28.176 24.008 28.2 ;
     RECT  22.549 40.08 24.008 40.104 ;
     RECT  24.001 41.136 24.008 41.16 ;
     RECT  22.595 42.24 24.008 42.264 ;
     RECT  22.811 47.04 24.008 48.264 ;
     RECT  18.904 49.536 24.008 49.56 ;
     RECT  24.008 1.728 24.112 49.692 ;
     RECT  24.112 1.728 24.304 49.56 ;
     RECT  24.304 41.136 24.419 41.208 ;
     RECT  24.304 46.224 24.419 47.736 ;
     RECT  24.304 42.24 24.445 43.368 ;
     RECT  24.304 38.496 24.467 38.76 ;
     RECT  24.304 2.832 24.515 3.96 ;
     RECT  24.515 3.408 24.941 3.96 ;
     RECT  24.304 26.304 24.941 26.424 ;
     RECT  24.304 27.936 25.139 28.2 ;
     RECT  24.304 39.888 25.265 40.104 ;
     RECT  24.304 12.432 25.283 13.128 ;
     RECT  24.941 26.4 25.283 26.424 ;
     RECT  25.139 27.936 25.283 27.96 ;
     RECT  24.419 46.752 25.405 47.736 ;
     RECT  25.405 10.752 25.489 10.776 ;
     RECT  24.419 41.184 25.585 41.208 ;
     RECT  24.445 42.24 25.585 43.224 ;
     RECT  25.585 41.184 25.693 43.224 ;
     RECT  25.657 0.576 25.741 0.6 ;
     RECT  24.941 3.936 25.765 3.96 ;
     RECT  24.467 38.544 25.765 38.76 ;
     RECT  25.765 38.544 25.801 38.808 ;
     RECT  25.724 2.736 25.811 2.76 ;
     RECT  25.765 3.936 25.859 4.248 ;
     RECT  25.693 41.136 25.868 43.224 ;
     RECT  25.801 37.584 25.909 38.808 ;
     RECT  25.265 39.888 25.909 39.912 ;
     RECT  24.304 44.976 25.909 45 ;
     RECT  25.813 10.848 25.913 10.872 ;
     RECT  25.868 41.136 25.945 43.32 ;
     RECT  25.405 46.752 25.945 48.12 ;
     RECT  25.945 41.136 26.051 43.944 ;
     RECT  26.051 41.136 26.125 43.32 ;
     RECT  25.909 44.976 26.197 45.48 ;
     RECT  25.909 37.584 26.245 39.912 ;
     RECT  26.125 41.088 26.245 43.32 ;
     RECT  26.197 44.976 26.293 45.528 ;
     RECT  25.945 46.512 26.293 48.12 ;
     RECT  26.245 37.584 26.337 43.32 ;
     RECT  26.337 37.584 26.417 39.288 ;
     RECT  24.304 49.536 26.533 49.56 ;
     RECT  26.293 44.976 26.544 48.12 ;
     RECT  26.533 49.488 26.633 49.56 ;
     RECT  26.337 40.8 26.741 43.32 ;
     RECT  25.283 12.432 27.281 12.456 ;
     RECT  26.741 41.568 27.385 43.32 ;
     RECT  26.417 38.448 27.421 39.288 ;
     RECT  27.385 41.568 27.497 43.512 ;
     RECT  25.859 3.936 27.529 3.96 ;
     RECT  27.421 38.112 27.601 39.288 ;
     RECT  27.601 37.968 27.733 39.288 ;
     RECT  27.733 37.968 27.821 39.384 ;
     RECT  26.544 45.504 28.141 48.12 ;
     RECT  27.529 3.936 28.177 4.104 ;
     RECT  28.141 45.216 28.177 48.12 ;
     RECT  28.177 45.12 28.181 48.12 ;
     RECT  26.633 49.536 28.307 49.56 ;
     RECT  28.181 45.12 28.405 45.24 ;
     RECT  28.177 3.312 28.693 4.104 ;
     RECT  27.497 41.568 28.741 43.32 ;
     RECT  28.405 44.448 28.741 45.24 ;
     RECT  27.565 36.912 29.041 36.936 ;
     RECT  27.821 37.968 29.041 39.288 ;
     RECT  24.304 1.728 29.197 1.752 ;
     RECT  29.041 36.912 29.221 39.288 ;
     RECT  28.741 40.944 29.221 45.24 ;
     RECT  28.693 2.832 29.408 4.104 ;
     RECT  28.537 12 29.408 12.936 ;
     RECT  28.741 25.488 29.408 25.512 ;
     RECT  29.221 36.432 29.408 45.24 ;
     RECT  28.181 46.224 29.408 48.12 ;
     RECT  28.693 49.344 29.408 49.512 ;
     RECT  29.408 2.148 29.512 49.692 ;
     RECT  29.512 2.418 29.545 49.692 ;
     RECT  29.545 2.418 29.629 49.8 ;
     RECT  29.629 2.418 29.704 49.56 ;
     RECT  29.704 2.832 29.729 2.856 ;
     RECT  29.704 3.936 29.765 3.96 ;
     RECT  29.704 25.488 29.801 25.608 ;
     RECT  29.704 40.944 29.945 44.136 ;
     RECT  29.704 36.912 30.233 39.72 ;
     RECT  29.945 41.136 30.349 44.136 ;
     RECT  29.704 45.12 30.364 45.24 ;
     RECT  29.704 46.224 30.413 48.264 ;
     RECT  30.413 47.04 30.557 48.264 ;
     RECT  30.233 38.16 30.563 39.72 ;
     RECT  30.563 38.16 30.604 38.184 ;
     RECT  30.563 39.696 30.665 39.72 ;
     RECT  30.349 41.136 30.737 42.552 ;
     RECT  30.737 41.424 30.809 42.552 ;
     RECT  30.349 43.776 30.809 44.136 ;
     RECT  30.809 41.616 30.917 42.552 ;
     RECT  30.809 44.112 31.169 44.136 ;
     RECT  30.557 47.04 31.205 48.12 ;
     RECT  29.704 49.536 31.285 49.56 ;
     RECT  30.233 36.912 31.345 36.936 ;
     RECT  31.273 45.552 31.379 45.576 ;
     RECT  31.345 36.24 31.385 36.936 ;
     RECT  31.205 47.376 31.493 48.12 ;
     RECT  31.385 36.24 31.571 36.264 ;
     RECT  30.917 41.616 31.673 41.976 ;
     RECT  31.285 49.488 31.853 49.56 ;
     RECT  31.705 38.784 31.861 39.336 ;
     RECT  31.493 47.904 31.889 48.12 ;
     RECT  31.597 37.584 31.907 37.608 ;
     RECT  31.861 38.64 31.961 39.336 ;
     RECT  31.961 38.784 31.997 39.336 ;
     RECT  31.853 49.488 32.249 49.512 ;
     RECT  32.461 50.736 32.627 50.76 ;
     RECT  32.893 49.536 33.445 49.56 ;
     RECT  31.889 47.904 33.541 47.928 ;
     RECT  33.445 49.488 33.545 49.56 ;
     RECT  33.541 47.904 33.581 48.264 ;
     RECT  31.673 41.616 33.779 41.64 ;
     RECT  31.997 39.312 33.82 39.336 ;
     RECT  33.581 48.24 34.621 48.264 ;
     RECT  33.545 49.536 34.7 49.56 ;
     RECT  34.7 49.536 34.787 49.848 ;
     RECT  29.801 25.584 34.808 25.608 ;
     RECT  31.525 27.312 34.808 27.336 ;
     RECT  34.621 48.24 34.808 48.408 ;
     RECT  34.787 49.536 34.808 49.692 ;
     RECT  34.808 2.148 34.912 49.692 ;
     RECT  34.912 2.418 35.104 49.56 ;
     RECT  35.104 49.488 35.273 49.56 ;
     RECT  35.104 48.384 35.813 48.408 ;
     RECT  35.273 49.536 36.083 49.56 ;
     RECT  36.428 50.736 36.515 50.76 ;
     RECT  35.104 25.584 40.208 25.608 ;
     RECT  35.104 27.312 40.208 27.336 ;
     RECT  40.208 2.148 40.312 49.692 ;
     RECT  40.312 2.418 40.504 49.422 ;
     RECT  40.504 27.312 43.945 27.336 ;
     RECT  43.945 27.216 43.985 27.336 ;
     RECT  40.504 25.584 44.453 25.608 ;
     RECT  43.985 27.216 45.493 27.24 ;
     RECT  44.953 25.008 45.608 25.032 ;
     RECT  45.493 26.352 45.608 27.384 ;
     RECT  45.608 2.148 45.712 49.692 ;
     RECT  45.712 2.418 45.904 49.422 ;
     RECT  45.904 24.48 46.499 25.032 ;
     RECT  46.499 24.48 46.541 24.504 ;
     RECT  45.904 26.016 46.541 26.04 ;
     RECT  45.904 27.36 46.649 27.384 ;
     RECT  50.605 27.168 50.641 27.192 ;
     RECT  49.201 25.008 50.677 25.032 ;
     RECT  50.641 26.736 50.677 27.192 ;
     RECT  50.677 24.144 51.804 27.624 ;
    LAYER M5 ;
     RECT  22.656 0.016 29.16 1.763 ;
     RECT  2.4 2.137 2.52 2.151 ;
     RECT  7.8 2.137 7.92 2.151 ;
     RECT  13.2 2.137 13.32 2.151 ;
     RECT  18.6 2.137 18.72 2.151 ;
     RECT  29.4 2.137 29.52 2.151 ;
     RECT  34.8 2.137 34.92 2.151 ;
     RECT  40.2 2.137 40.32 2.151 ;
     RECT  45.6 2.137 45.72 2.151 ;
     RECT  24 1.763 24.312 2.821 ;
     RECT  29.4 2.151 29.712 2.821 ;
     RECT  24 2.821 24.504 3.443 ;
     RECT  22.752 2.821 22.776 3.685 ;
     RECT  22.464 3.685 22.776 3.731 ;
     RECT  25.776 2.725 25.8 4.213 ;
     RECT  25.776 4.213 25.848 10.741 ;
     RECT  2.4 2.151 2.712 10.789 ;
     RECT  25.44 10.741 25.848 10.883 ;
     RECT  7.8 2.151 8.112 11.461 ;
     RECT  24 3.443 24.456 12.421 ;
     RECT  25.44 10.883 25.8 12.421 ;
     RECT  22.464 3.731 22.488 12.803 ;
     RECT  7.8 11.461 8.232 13.573 ;
     RECT  4.8 12.757 4.824 14.675 ;
     RECT  7.68 13.573 8.232 15.443 ;
     RECT  2.4 10.789 3.336 19.235 ;
     RECT  7.68 15.443 8.112 19.237 ;
     RECT  5.04 19.621 5.064 19.909 ;
     RECT  6.432 16.837 6.456 20.003 ;
     RECT  4.56 19.909 5.064 21.395 ;
     RECT  7.68 19.237 8.232 22.259 ;
     RECT  4.944 21.395 5.064 22.835 ;
     RECT  7.68 22.259 8.112 23.699 ;
     RECT  45.6 2.151 45.912 24.469 ;
     RECT  5.04 22.835 5.064 25.045 ;
     RECT  45.6 24.469 46.488 26.051 ;
     RECT  7.8 23.699 8.112 26.197 ;
     RECT  45.6 26.051 45.912 26.341 ;
     RECT  4.848 25.045 5.064 27.107 ;
     RECT  45.504 26.341 45.912 27.395 ;
     RECT  7.8 26.197 8.232 27.731 ;
     RECT  5.04 27.107 5.064 28.453 ;
     RECT  4.896 28.453 5.064 28.693 ;
     RECT  4.896 28.693 5.112 28.835 ;
     RECT  4.896 28.835 5.016 28.883 ;
     RECT  4.992 28.883 5.016 29.123 ;
     RECT  7.8 27.731 8.112 30.421 ;
     RECT  4.56 29.989 4.584 31.667 ;
     RECT  7.8 30.421 8.232 32.051 ;
     RECT  7.8 32.051 8.112 34.357 ;
     RECT  9.216 28.453 9.24 34.357 ;
     RECT  7.8 34.357 9.24 35.315 ;
     RECT  6.288 34.117 6.312 35.363 ;
     RECT  31.536 27.301 31.56 36.275 ;
     RECT  24 12.421 25.8 37.573 ;
     RECT  9.216 35.315 9.24 37.619 ;
     RECT  7.8 35.315 8.232 37.957 ;
     RECT  28.704 2.821 29.712 38.149 ;
     RECT  7.68 37.957 8.232 38.195 ;
     RECT  24 37.573 26.28 38.533 ;
     RECT  31.872 37.573 31.896 38.675 ;
     RECT  24 38.533 26.76 38.723 ;
     RECT  27.744 38.149 30.552 38.819 ;
     RECT  7.68 38.195 8.112 39.205 ;
     RECT  27.744 38.819 27.768 39.395 ;
     RECT  4.8 36.901 4.824 40.307 ;
     RECT  7.44 39.205 8.112 40.595 ;
     RECT  33.744 39.301 33.768 41.651 ;
     RECT  28.752 38.819 30.552 41.701 ;
     RECT  22.56 40.069 22.584 42.419 ;
     RECT  18.6 2.151 18.912 42.469 ;
     RECT  27.936 41.701 30.552 42.469 ;
     RECT  24 38.723 26.328 43.379 ;
     RECT  27.936 42.469 30.696 43.811 ;
     RECT  18.096 42.469 18.912 44.483 ;
     RECT  27.936 43.811 30.312 44.483 ;
     RECT  24 43.379 24.312 44.965 ;
     RECT  25.344 43.379 26.328 44.965 ;
     RECT  29.4 44.483 30.312 45.155 ;
     RECT  18.6 44.483 18.912 45.301 ;
     RECT  24 44.965 26.472 45.731 ;
     RECT  24 45.731 26.328 46.259 ;
     RECT  25.344 46.259 26.328 46.307 ;
     RECT  27.936 44.483 27.96 46.741 ;
     RECT  25.344 46.307 25.608 46.787 ;
     RECT  27.936 46.741 28.2 46.787 ;
     RECT  31.344 45.541 31.368 47.125 ;
     RECT  25.488 46.787 25.608 47.171 ;
     RECT  28.176 46.787 28.2 47.315 ;
     RECT  30.72 47.125 31.368 47.843 ;
     RECT  18.6 45.301 19.176 47.891 ;
     RECT  30.72 47.843 30.744 48.131 ;
     RECT  22.752 47.557 22.776 48.275 ;
     RECT  21.12 42.373 21.144 48.515 ;
     RECT  15.312 26.293 15.336 48.997 ;
     RECT  29.4 45.155 29.712 49.333 ;
     RECT  15.312 48.997 15.768 49.477 ;
     RECT  34.8 2.151 35.112 49.477 ;
     RECT  15.312 49.477 16.632 49.525 ;
     RECT  18.6 47.891 18.912 49.525 ;
     RECT  24 46.259 24.312 49.525 ;
     RECT  26.544 49.477 26.568 49.525 ;
     RECT  28.704 49.333 29.712 49.525 ;
     RECT  31.296 49.477 32.184 49.525 ;
     RECT  33.456 49.477 33.48 49.525 ;
     RECT  34.8 49.477 35.208 49.525 ;
     RECT  2.4 19.235 2.712 49.689 ;
     RECT  7.8 40.595 8.112 49.689 ;
     RECT  13.2 2.151 13.512 49.689 ;
     RECT  40.2 2.151 40.512 49.689 ;
     RECT  45.6 27.395 45.912 49.689 ;
     RECT  2.4 49.689 2.52 49.703 ;
     RECT  7.8 49.689 7.92 49.703 ;
     RECT  13.2 49.689 13.32 49.703 ;
     RECT  40.2 49.689 40.32 49.703 ;
     RECT  45.6 49.689 45.72 49.703 ;
     RECT  15.312 49.525 36.072 50.725 ;
     RECT  15.312 50.725 36.504 51.792 ;
     RECT  22.752 1.763 24 2.821 ;
     RECT  24.312 1.763 25.8 2.725 ;
     RECT  28.704 1.763 29.16 2.137 ;
     RECT  28.704 2.137 29.4 2.821 ;
     RECT  24.312 2.725 25.776 2.821 ;
     RECT  22.776 2.821 24 3.731 ;
     RECT  24.504 2.821 25.776 3.443 ;
     RECT  24.456 3.443 25.776 10.741 ;
     RECT  22.488 3.731 24 12.803 ;
     RECT  24.456 10.741 25.44 12.421 ;
     RECT  3.336 12.757 4.8 14.675 ;
     RECT  6.456 16.837 7.68 20.003 ;
     RECT  5.064 19.621 6.432 20.003 ;
     RECT  4.896 27.107 5.04 28.453 ;
     RECT  8.112 27.731 8.232 28.453 ;
     RECT  8.112 28.453 9.216 30.421 ;
     RECT  8.232 30.421 9.216 32.051 ;
     RECT  8.112 32.051 9.216 34.357 ;
     RECT  6.312 34.117 7.8 35.363 ;
     RECT  8.232 35.315 9.216 37.619 ;
     RECT  26.28 38.149 27.744 38.533 ;
     RECT  30.552 38.149 31.872 38.675 ;
     RECT  26.76 38.533 27.744 38.723 ;
     RECT  26.328 38.723 27.744 39.395 ;
     RECT  27.768 38.819 28.752 39.395 ;
     RECT  33.768 39.301 34.8 41.651 ;
     RECT  22.584 40.069 24 42.419 ;
     RECT  21.144 42.373 22.56 42.419 ;
     RECT  24.312 43.379 25.344 44.965 ;
     RECT  27.96 44.483 29.4 46.741 ;
     RECT  26.472 44.965 27.936 45.731 ;
     RECT  24.312 46.259 25.344 46.787 ;
     RECT  28.2 46.741 29.4 47.315 ;
     RECT  24.312 46.787 25.488 47.171 ;
     RECT  29.712 47.125 30.72 48.131 ;
     RECT  22.776 47.557 24 48.275 ;
     RECT  29.712 48.131 30.744 49.477 ;
     RECT  22.752 48.275 24 49.525 ;
     RECT  21.12 48.515 21.144 49.525 ;
     RECT  29.712 49.477 31.296 49.525 ;
     RECT  32.184 49.477 33.456 49.525 ;
     RECT  33.48 49.477 34.8 49.525 ;
  END
END dsfd_vm_static_read_v3_p
END LIBRARY
